VERSION 5.7 ;
  NOWIREEXTENSIONATPIN ON ;
  DIVIDERCHAR "/" ;
  BUSBITCHARS "[]" ;
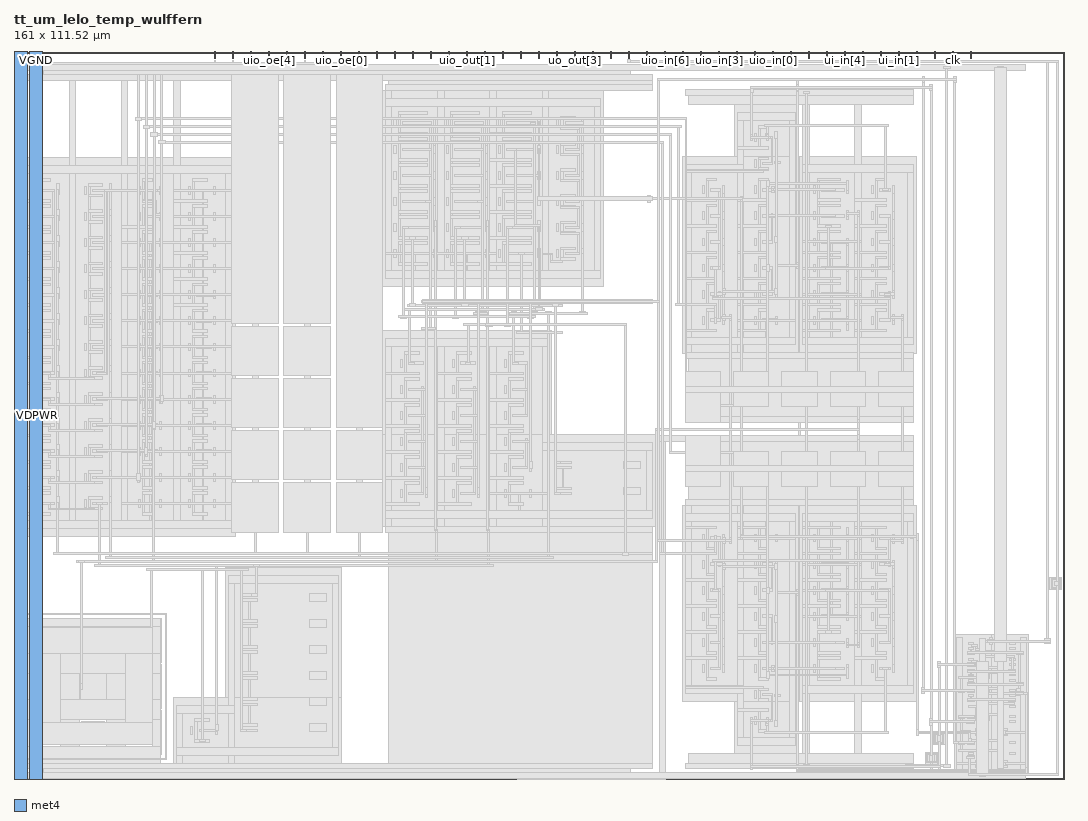
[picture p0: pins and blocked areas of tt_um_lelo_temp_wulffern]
MACRO tt_um_lelo_temp_wulffern
  CLASS BLOCK ;
  FOREIGN tt_um_lelo_temp_wulffern ;
  ORIGIN 0.000 0.000 ;
  SIZE 161.000 BY 111.520 ;
  PIN uio_oe[7]
    DIRECTION OUTPUT ;
    USE SIGNAL ;
    PORT
      LAYER met4 ;
        RECT 30.670 110.520 30.970 111.520 ;
    END
  END uio_oe[7]
  PIN uio_oe[6]
    DIRECTION OUTPUT ;
    USE SIGNAL ;
    PORT
      LAYER met4 ;
        RECT 33.430 110.520 33.730 111.520 ;
    END
  END uio_oe[6]
  PIN uio_oe[5]
    DIRECTION OUTPUT ;
    USE SIGNAL ;
    PORT
      LAYER met4 ;
        RECT 36.190 110.520 36.490 111.520 ;
    END
  END uio_oe[5]
  PIN uio_oe[4]
    DIRECTION OUTPUT ;
    USE SIGNAL ;
    PORT
      LAYER met4 ;
        RECT 38.950 110.520 39.250 111.520 ;
    END
  END uio_oe[4]
  PIN uio_oe[3]
    DIRECTION OUTPUT ;
    USE SIGNAL ;
    PORT
      LAYER met4 ;
        RECT 41.710 110.520 42.010 111.520 ;
    END
  END uio_oe[3]
  PIN uio_oe[2]
    DIRECTION OUTPUT ;
    USE SIGNAL ;
    PORT
      LAYER met4 ;
        RECT 44.470 110.520 44.770 111.520 ;
    END
  END uio_oe[2]
  PIN uio_oe[1]
    DIRECTION OUTPUT ;
    USE SIGNAL ;
    PORT
      LAYER met4 ;
        RECT 47.230 110.520 47.530 111.520 ;
    END
  END uio_oe[1]
  PIN uio_oe[0]
    DIRECTION OUTPUT ;
    USE SIGNAL ;
    PORT
      LAYER met4 ;
        RECT 49.990 110.520 50.290 111.520 ;
    END
  END uio_oe[0]
  PIN VDPWR
    DIRECTION INOUT ;
    USE POWER ;
    PORT
      LAYER met4 ;
        RECT 0.000 0.000 2.000 111.520 ;
    END
  END VDPWR
  PIN VGND
    DIRECTION INOUT ;
    USE GROUND ;
    PORT
      LAYER met4 ;
        RECT 2.400 0.000 4.400 111.520 ;
    END
  END VGND
  PIN ui_in[7]
    DIRECTION INPUT ;
    USE SIGNAL ;
    PORT
      LAYER met4 ;
        RECT 118.990 110.520 119.290 111.520 ;
    END
  END ui_in[7]
  PIN ui_in[6]
    DIRECTION INPUT ;
    USE SIGNAL ;
    PORT
      LAYER met4 ;
        RECT 121.750 110.520 122.050 111.520 ;
    END
  END ui_in[6]
  PIN ui_in[5]
    DIRECTION INPUT ;
    USE SIGNAL ;
    PORT
      LAYER met4 ;
        RECT 124.510 110.520 124.810 111.520 ;
    END
  END ui_in[5]
  PIN ui_in[4]
    DIRECTION INPUT ;
    USE SIGNAL ;
    PORT
      LAYER met4 ;
        RECT 127.270 110.520 127.570 111.520 ;
    END
  END ui_in[4]
  PIN ui_in[3]
    DIRECTION INPUT ;
    USE SIGNAL ;
    PORT
      LAYER met4 ;
        RECT 130.030 110.520 130.330 111.520 ;
    END
  END ui_in[3]
  PIN ui_in[2]
    DIRECTION INPUT ;
    USE SIGNAL ;
    PORT
      LAYER met4 ;
        RECT 132.790 110.520 133.090 111.520 ;
    END
  END ui_in[2]
  PIN ui_in[1]
    DIRECTION INPUT ;
    USE SIGNAL ;
    PORT
      LAYER met4 ;
        RECT 135.550 110.520 135.850 111.520 ;
    END
  END ui_in[1]
  PIN ui_in[0]
    DIRECTION INPUT ;
    USE SIGNAL ;
    ANTENNAGATEAREA 0.490500 ;
    ANTENNADIFFAREA 0.202500 ;
    PORT
      LAYER met4 ;
        RECT 138.310 110.520 138.610 111.520 ;
    END
  END ui_in[0]
  PIN uio_in[7]
    DIRECTION INPUT ;
    USE SIGNAL ;
    PORT
      LAYER met4 ;
        RECT 96.910 110.520 97.210 111.520 ;
    END
  END uio_in[7]
  PIN uio_in[6]
    DIRECTION INPUT ;
    USE SIGNAL ;
    PORT
      LAYER met4 ;
        RECT 99.670 110.520 99.970 111.520 ;
    END
  END uio_in[6]
  PIN uio_in[5]
    DIRECTION INPUT ;
    USE SIGNAL ;
    PORT
      LAYER met4 ;
        RECT 102.430 110.520 102.730 111.520 ;
    END
  END uio_in[5]
  PIN uio_in[4]
    DIRECTION INPUT ;
    USE SIGNAL ;
    PORT
      LAYER met4 ;
        RECT 105.190 110.520 105.490 111.520 ;
    END
  END uio_in[4]
  PIN uio_in[3]
    DIRECTION INPUT ;
    USE SIGNAL ;
    PORT
      LAYER met4 ;
        RECT 107.950 110.520 108.250 111.520 ;
    END
  END uio_in[3]
  PIN uio_in[2]
    DIRECTION INPUT ;
    USE SIGNAL ;
    PORT
      LAYER met4 ;
        RECT 110.710 110.520 111.010 111.520 ;
    END
  END uio_in[2]
  PIN uio_in[1]
    DIRECTION INPUT ;
    USE SIGNAL ;
    PORT
      LAYER met4 ;
        RECT 113.470 110.520 113.770 111.520 ;
    END
  END uio_in[1]
  PIN uio_in[0]
    DIRECTION INPUT ;
    USE SIGNAL ;
    PORT
      LAYER met4 ;
        RECT 116.230 110.520 116.530 111.520 ;
    END
  END uio_in[0]
  PIN ena
    DIRECTION INPUT ;
    USE SIGNAL ;
    PORT
      LAYER met4 ;
        RECT 146.590 110.520 146.890 111.520 ;
    END
  END ena
  PIN rst_n
    DIRECTION INPUT ;
    USE SIGNAL ;
    PORT
      LAYER met4 ;
        RECT 141.070 110.520 141.370 111.520 ;
    END
  END rst_n
  PIN clk
    DIRECTION INPUT ;
    USE SIGNAL ;
    PORT
      LAYER met4 ;
        RECT 143.830 110.520 144.130 111.520 ;
    END
  END clk
  PIN uo_out[7]
    DIRECTION OUTPUT ;
    USE SIGNAL ;
    PORT
      LAYER met4 ;
        RECT 74.830 110.520 75.130 111.520 ;
    END
  END uo_out[7]
  PIN uo_out[6]
    DIRECTION OUTPUT ;
    USE SIGNAL ;
    PORT
      LAYER met4 ;
        RECT 77.590 110.520 77.890 111.520 ;
    END
  END uo_out[6]
  PIN uo_out[5]
    DIRECTION OUTPUT ;
    USE SIGNAL ;
    PORT
      LAYER met4 ;
        RECT 80.350 110.520 80.650 111.520 ;
    END
  END uo_out[5]
  PIN uo_out[4]
    DIRECTION OUTPUT ;
    USE SIGNAL ;
    PORT
      LAYER met4 ;
        RECT 83.110 110.520 83.410 111.520 ;
    END
  END uo_out[4]
  PIN uo_out[3]
    DIRECTION OUTPUT ;
    USE SIGNAL ;
    PORT
      LAYER met4 ;
        RECT 85.870 110.520 86.170 111.520 ;
    END
  END uo_out[3]
  PIN uo_out[2]
    DIRECTION OUTPUT ;
    USE SIGNAL ;
    PORT
      LAYER met4 ;
        RECT 88.630 110.520 88.930 111.520 ;
    END
  END uo_out[2]
  PIN uo_out[1]
    DIRECTION OUTPUT ;
    USE SIGNAL ;
    PORT
      LAYER met4 ;
        RECT 91.390 110.520 91.690 111.520 ;
    END
  END uo_out[1]
  PIN uo_out[0]
    DIRECTION OUTPUT ;
    USE SIGNAL ;
    ANTENNADIFFAREA 0.936000 ;
    PORT
      LAYER met4 ;
        RECT 94.150 110.520 94.450 111.520 ;
    END
  END uo_out[0]
  PIN uio_out[7]
    DIRECTION OUTPUT ;
    USE SIGNAL ;
    PORT
      LAYER met4 ;
        RECT 52.750 110.520 53.050 111.520 ;
    END
  END uio_out[7]
  PIN uio_out[6]
    DIRECTION OUTPUT ;
    USE SIGNAL ;
    PORT
      LAYER met4 ;
        RECT 55.510 110.520 55.810 111.520 ;
    END
  END uio_out[6]
  PIN uio_out[5]
    DIRECTION OUTPUT ;
    USE SIGNAL ;
    PORT
      LAYER met4 ;
        RECT 58.270 110.520 58.570 111.520 ;
    END
  END uio_out[5]
  PIN uio_out[4]
    DIRECTION OUTPUT ;
    USE SIGNAL ;
    PORT
      LAYER met4 ;
        RECT 61.030 110.520 61.330 111.520 ;
    END
  END uio_out[4]
  PIN uio_out[3]
    DIRECTION OUTPUT ;
    USE SIGNAL ;
    PORT
      LAYER met4 ;
        RECT 63.790 110.520 64.090 111.520 ;
    END
  END uio_out[3]
  PIN uio_out[2]
    DIRECTION OUTPUT ;
    USE SIGNAL ;
    PORT
      LAYER met4 ;
        RECT 66.550 110.520 66.850 111.520 ;
    END
  END uio_out[2]
  PIN uio_out[1]
    DIRECTION OUTPUT ;
    USE SIGNAL ;
    PORT
      LAYER met4 ;
        RECT 69.310 110.520 69.610 111.520 ;
    END
  END uio_out[1]
  PIN uio_out[0]
    DIRECTION OUTPUT ;
    USE SIGNAL ;
    PORT
      LAYER met4 ;
        RECT 72.070 110.520 72.370 111.520 ;
    END
  END uio_out[0]
  OBS
      LAYER nwell ;
        RECT 0.060 37.210 33.900 95.290 ;
        RECT 56.540 75.510 90.380 105.590 ;
      LAYER pwell ;
        RECT 110.500 95.390 120.340 103.390 ;
        RECT 56.540 52.790 82.380 68.790 ;
        RECT 102.500 65.310 120.340 95.390 ;
      LAYER nwell ;
        RECT 120.500 65.310 138.340 95.390 ;
      LAYER pwell ;
        RECT 56.540 38.710 98.380 52.790 ;
        RECT 1.665 23.870 8.365 24.635 ;
        RECT 1.665 18.700 2.430 23.870 ;
        RECT 7.600 18.700 8.365 23.870 ;
        RECT 1.665 17.935 8.365 18.700 ;
        RECT 8.765 23.870 15.465 24.635 ;
        RECT 8.765 18.700 9.530 23.870 ;
        RECT 14.700 18.700 15.465 23.870 ;
        RECT 8.765 17.935 15.465 18.700 ;
        RECT 15.865 23.870 22.565 24.635 ;
        RECT 15.865 18.700 16.630 23.870 ;
        RECT 21.800 18.700 22.565 23.870 ;
        RECT 15.865 17.935 22.565 18.700 ;
        RECT 1.665 16.770 8.365 17.535 ;
        RECT 1.665 11.600 2.430 16.770 ;
        RECT 7.600 11.600 8.365 16.770 ;
        RECT 1.665 10.835 8.365 11.600 ;
        RECT 8.765 16.770 15.465 17.535 ;
        RECT 8.765 11.600 9.530 16.770 ;
        RECT 14.700 11.600 15.465 16.770 ;
        RECT 8.765 10.835 15.465 11.600 ;
        RECT 15.865 16.770 22.565 17.535 ;
        RECT 15.865 11.600 16.630 16.770 ;
        RECT 21.800 11.600 22.565 16.770 ;
        RECT 32.430 12.490 50.270 32.490 ;
        RECT 15.865 10.835 22.565 11.600 ;
        RECT 1.665 9.670 8.365 10.435 ;
        RECT 1.665 4.500 2.430 9.670 ;
        RECT 7.600 4.500 8.365 9.670 ;
        RECT 1.665 3.735 8.365 4.500 ;
        RECT 8.765 9.670 15.465 10.435 ;
        RECT 8.765 4.500 9.530 9.670 ;
        RECT 14.700 4.500 15.465 9.670 ;
        RECT 8.765 3.735 15.465 4.500 ;
        RECT 15.865 9.670 22.565 10.435 ;
        RECT 15.865 4.500 16.630 9.670 ;
        RECT 21.800 4.500 22.565 9.670 ;
        RECT 15.865 3.735 22.565 4.500 ;
        RECT 24.430 2.410 50.270 12.490 ;
        RECT 102.500 11.910 120.340 41.990 ;
      LAYER nwell ;
        RECT 120.500 11.910 138.340 41.990 ;
      LAYER pwell ;
        RECT 158.835 29.085 160.665 30.915 ;
        RECT 110.500 3.910 120.340 11.910 ;
        RECT 140.925 5.285 142.755 7.115 ;
        RECT 139.725 2.285 141.555 4.115 ;
        RECT 144.190 0.950 149.890 22.150 ;
      LAYER nwell ;
        RECT 149.890 0.950 155.590 22.150 ;
      LAYER li1 ;
        RECT 0.500 108.610 155.020 109.510 ;
        RECT 4.460 107.950 94.460 108.610 ;
        RECT 0.500 107.050 97.940 107.950 ;
        RECT 0.500 94.050 1.460 107.050 ;
        RECT 8.500 94.050 9.460 107.050 ;
        RECT 16.500 94.050 17.460 107.050 ;
        RECT 24.500 94.050 25.460 107.050 ;
        RECT 57.460 106.450 97.940 107.050 ;
        RECT 56.980 105.550 97.940 106.450 ;
        RECT 56.980 104.350 57.940 105.550 ;
        RECT 64.980 104.350 65.940 105.550 ;
        RECT 72.980 104.350 73.940 105.550 ;
        RECT 80.980 104.350 81.940 105.550 ;
        RECT 102.940 104.850 137.940 105.750 ;
        RECT 56.980 103.150 89.940 104.350 ;
        RECT 103.420 103.350 137.900 104.850 ;
        RECT 0.500 92.850 33.460 94.050 ;
        RECT 0.500 88.850 1.460 92.850 ;
        RECT 3.380 91.650 5.620 92.050 ;
        RECT 2.740 89.650 3.060 90.850 ;
        RECT 3.380 88.850 3.700 91.650 ;
        RECT 6.570 90.850 6.890 91.290 ;
        RECT 6.570 90.450 6.900 90.850 ;
        RECT 4.020 90.050 6.260 90.450 ;
        RECT 0.500 88.450 5.620 88.850 ;
        RECT 0.500 84.850 1.460 88.450 ;
        RECT 3.380 87.650 5.620 88.050 ;
        RECT 2.740 85.650 3.060 86.850 ;
        RECT 3.380 84.850 3.700 87.650 ;
        RECT 5.960 86.450 6.260 90.050 ;
        RECT 6.580 89.650 6.900 90.450 ;
        RECT 6.590 87.290 6.890 89.650 ;
        RECT 6.570 86.850 6.890 87.290 ;
        RECT 6.570 86.450 6.900 86.850 ;
        RECT 4.020 86.050 6.260 86.450 ;
        RECT 0.500 84.450 5.620 84.850 ;
        RECT 0.500 80.850 1.460 84.450 ;
        RECT 3.380 83.650 5.620 84.050 ;
        RECT 2.740 81.650 3.060 82.850 ;
        RECT 3.380 80.850 3.700 83.650 ;
        RECT 5.960 82.450 6.260 86.050 ;
        RECT 6.580 85.650 6.900 86.450 ;
        RECT 6.590 83.290 6.890 85.650 ;
        RECT 6.570 82.850 6.890 83.290 ;
        RECT 6.570 82.450 6.900 82.850 ;
        RECT 4.020 82.050 6.260 82.450 ;
        RECT 0.500 80.450 5.620 80.850 ;
        RECT 0.500 76.850 1.460 80.450 ;
        RECT 3.380 79.650 5.620 80.050 ;
        RECT 2.740 77.650 3.060 78.850 ;
        RECT 3.380 76.850 3.700 79.650 ;
        RECT 5.960 78.450 6.260 82.050 ;
        RECT 6.580 81.650 6.900 82.450 ;
        RECT 6.590 79.290 6.890 81.650 ;
        RECT 6.570 78.850 6.890 79.290 ;
        RECT 6.570 78.450 6.900 78.850 ;
        RECT 4.020 78.050 6.260 78.450 ;
        RECT 0.500 76.450 5.620 76.850 ;
        RECT 0.500 72.850 1.460 76.450 ;
        RECT 3.380 75.650 5.620 76.050 ;
        RECT 2.740 73.650 3.060 74.850 ;
        RECT 3.380 72.850 3.700 75.650 ;
        RECT 5.960 74.450 6.260 78.050 ;
        RECT 6.580 77.650 6.900 78.450 ;
        RECT 6.590 75.290 6.890 77.650 ;
        RECT 6.570 74.850 6.890 75.290 ;
        RECT 6.570 74.450 6.900 74.850 ;
        RECT 4.020 74.050 6.260 74.450 ;
        RECT 0.500 72.450 5.620 72.850 ;
        RECT 0.500 68.850 1.460 72.450 ;
        RECT 3.380 71.650 5.620 72.050 ;
        RECT 2.740 69.650 3.060 70.850 ;
        RECT 3.380 68.850 3.700 71.650 ;
        RECT 5.960 70.450 6.260 74.050 ;
        RECT 6.580 73.650 6.900 74.450 ;
        RECT 6.590 71.290 6.890 73.650 ;
        RECT 6.570 70.850 6.890 71.290 ;
        RECT 6.570 70.450 6.900 70.850 ;
        RECT 4.020 70.050 6.260 70.450 ;
        RECT 0.500 68.450 5.620 68.850 ;
        RECT 0.500 64.850 1.460 68.450 ;
        RECT 3.380 67.650 5.620 68.050 ;
        RECT 2.740 65.650 3.060 66.850 ;
        RECT 3.380 64.850 3.700 67.650 ;
        RECT 5.960 66.450 6.260 70.050 ;
        RECT 6.580 69.650 6.900 70.450 ;
        RECT 6.590 67.290 6.890 69.650 ;
        RECT 6.570 66.850 6.890 67.290 ;
        RECT 6.570 66.450 6.900 66.850 ;
        RECT 4.020 66.050 6.260 66.450 ;
        RECT 0.500 64.450 5.620 64.850 ;
        RECT 0.500 60.850 1.460 64.450 ;
        RECT 3.380 63.650 5.620 64.050 ;
        RECT 2.740 61.650 3.060 62.850 ;
        RECT 3.380 60.850 3.700 63.650 ;
        RECT 5.960 62.450 6.260 66.050 ;
        RECT 6.580 65.650 6.900 66.450 ;
        RECT 6.590 63.290 6.890 65.650 ;
        RECT 6.570 62.850 6.890 63.290 ;
        RECT 6.570 62.450 6.900 62.850 ;
        RECT 4.020 62.050 6.260 62.450 ;
        RECT 6.580 61.650 6.900 62.450 ;
        RECT 0.500 60.450 5.620 60.850 ;
        RECT 0.500 56.850 1.460 60.450 ;
        RECT 3.380 59.650 5.620 60.050 ;
        RECT 2.740 57.650 3.060 58.850 ;
        RECT 3.380 56.850 3.700 59.650 ;
        RECT 6.590 59.290 6.890 61.650 ;
        RECT 6.570 58.850 6.890 59.290 ;
        RECT 6.570 58.450 6.900 58.850 ;
        RECT 4.020 58.050 6.260 58.450 ;
        RECT 6.580 57.650 6.900 58.450 ;
        RECT 0.500 56.450 5.620 56.850 ;
        RECT 0.500 52.850 1.460 56.450 ;
        RECT 3.380 55.650 5.620 56.050 ;
        RECT 2.740 53.650 3.060 54.850 ;
        RECT 3.380 52.850 3.700 55.650 ;
        RECT 6.590 55.290 6.890 57.650 ;
        RECT 6.570 54.850 6.890 55.290 ;
        RECT 6.570 54.450 6.900 54.850 ;
        RECT 4.020 54.050 6.260 54.450 ;
        RECT 6.580 53.650 6.900 54.450 ;
        RECT 0.500 52.450 5.620 52.850 ;
        RECT 0.500 48.850 1.460 52.450 ;
        RECT 3.380 51.650 5.620 52.050 ;
        RECT 2.740 49.650 3.060 50.850 ;
        RECT 3.380 48.850 3.700 51.650 ;
        RECT 6.590 51.290 6.890 53.650 ;
        RECT 6.570 50.850 6.890 51.290 ;
        RECT 6.570 50.450 6.900 50.850 ;
        RECT 4.020 50.050 6.260 50.450 ;
        RECT 6.580 49.650 6.900 50.450 ;
        RECT 0.500 48.450 5.620 48.850 ;
        RECT 0.500 44.850 1.460 48.450 ;
        RECT 3.380 47.650 5.620 48.050 ;
        RECT 2.740 45.650 3.060 46.850 ;
        RECT 3.380 44.850 3.700 47.650 ;
        RECT 6.590 47.290 6.890 49.650 ;
        RECT 6.570 46.850 6.890 47.290 ;
        RECT 6.570 46.450 6.900 46.850 ;
        RECT 4.020 46.050 6.260 46.450 ;
        RECT 6.580 45.650 6.900 46.450 ;
        RECT 0.500 44.450 5.620 44.850 ;
        RECT 0.500 40.850 1.460 44.450 ;
        RECT 3.380 43.650 5.620 44.050 ;
        RECT 2.740 41.650 3.060 42.850 ;
        RECT 3.380 40.850 3.700 43.650 ;
        RECT 6.590 43.290 6.890 45.650 ;
        RECT 6.570 42.850 6.890 43.290 ;
        RECT 6.570 42.450 6.900 42.850 ;
        RECT 4.020 42.050 6.260 42.450 ;
        RECT 6.580 41.650 6.900 42.450 ;
        RECT 0.500 40.450 5.620 40.850 ;
        RECT 0.500 39.650 1.460 40.450 ;
        RECT 8.500 39.650 9.460 92.850 ;
        RECT 11.380 90.850 13.620 91.250 ;
        RECT 14.570 90.850 14.890 91.290 ;
        RECT 10.740 89.650 11.060 90.850 ;
        RECT 11.380 89.650 11.700 90.850 ;
        RECT 14.570 90.450 14.900 90.850 ;
        RECT 12.020 90.050 14.260 90.450 ;
        RECT 11.380 89.250 13.620 89.650 ;
        RECT 11.380 87.250 11.680 89.250 ;
        RECT 11.380 86.850 13.620 87.250 ;
        RECT 10.740 85.650 11.060 86.850 ;
        RECT 11.380 85.650 11.700 86.850 ;
        RECT 13.960 86.450 14.260 90.050 ;
        RECT 14.580 89.650 14.900 90.450 ;
        RECT 14.590 87.290 14.890 89.650 ;
        RECT 14.570 86.850 14.890 87.290 ;
        RECT 14.570 86.450 14.900 86.850 ;
        RECT 12.020 86.050 14.260 86.450 ;
        RECT 11.380 85.250 13.620 85.650 ;
        RECT 11.380 83.250 11.680 85.250 ;
        RECT 11.380 82.850 13.620 83.250 ;
        RECT 10.740 81.650 11.060 82.850 ;
        RECT 11.380 81.650 11.700 82.850 ;
        RECT 13.960 82.450 14.260 86.050 ;
        RECT 14.580 85.650 14.900 86.450 ;
        RECT 14.590 83.290 14.890 85.650 ;
        RECT 14.570 82.850 14.890 83.290 ;
        RECT 16.500 84.850 17.460 92.850 ;
        RECT 19.700 91.650 21.300 92.050 ;
        RECT 19.060 89.650 19.380 90.850 ;
        RECT 19.700 88.850 20.020 91.650 ;
        RECT 22.260 90.450 22.580 90.850 ;
        RECT 20.340 90.050 22.580 90.450 ;
        RECT 22.260 89.650 22.580 90.050 ;
        RECT 24.500 90.400 25.460 92.850 ;
        RECT 27.380 91.650 29.620 92.050 ;
        RECT 26.740 90.400 27.060 90.850 ;
        RECT 27.380 90.400 27.700 91.650 ;
        RECT 30.580 90.450 30.900 90.850 ;
        RECT 28.020 90.400 30.900 90.450 ;
        RECT 32.500 90.400 33.460 92.850 ;
        RECT 24.500 90.100 33.460 90.400 ;
        RECT 24.500 88.850 25.460 90.100 ;
        RECT 26.740 89.650 27.060 90.100 ;
        RECT 27.380 88.850 27.700 90.100 ;
        RECT 28.020 90.050 30.900 90.100 ;
        RECT 28.830 88.850 29.130 90.050 ;
        RECT 30.580 89.650 30.900 90.050 ;
        RECT 19.700 88.750 21.300 88.850 ;
        RECT 19.700 88.450 21.900 88.750 ;
        RECT 19.700 87.650 21.300 88.050 ;
        RECT 19.060 85.650 19.380 86.850 ;
        RECT 19.700 84.850 20.020 87.650 ;
        RECT 21.600 86.750 21.900 88.450 ;
        RECT 24.500 88.450 29.620 88.850 ;
        RECT 22.260 86.750 22.580 86.850 ;
        RECT 21.600 86.450 22.580 86.750 ;
        RECT 20.340 86.050 22.580 86.450 ;
        RECT 22.260 85.650 22.580 86.050 ;
        RECT 24.500 86.400 25.460 88.450 ;
        RECT 28.830 88.050 29.130 88.450 ;
        RECT 27.380 87.650 29.620 88.050 ;
        RECT 26.740 86.400 27.060 86.850 ;
        RECT 27.380 86.400 27.700 87.650 ;
        RECT 28.830 86.450 29.130 87.650 ;
        RECT 30.580 86.450 30.900 86.850 ;
        RECT 28.020 86.400 30.900 86.450 ;
        RECT 32.500 86.400 33.460 90.100 ;
        RECT 24.500 86.100 33.460 86.400 ;
        RECT 24.500 84.850 25.460 86.100 ;
        RECT 26.740 85.650 27.060 86.100 ;
        RECT 27.380 84.850 27.700 86.100 ;
        RECT 28.020 86.050 30.900 86.100 ;
        RECT 28.830 84.850 29.130 86.050 ;
        RECT 30.580 85.650 30.900 86.050 ;
        RECT 16.500 84.450 21.300 84.850 ;
        RECT 24.500 84.450 29.620 84.850 ;
        RECT 14.570 82.450 14.900 82.850 ;
        RECT 12.020 82.050 14.260 82.450 ;
        RECT 11.380 81.250 13.620 81.650 ;
        RECT 11.380 79.250 11.680 81.250 ;
        RECT 11.380 78.850 13.620 79.250 ;
        RECT 10.740 77.650 11.060 78.850 ;
        RECT 11.380 77.650 11.700 78.850 ;
        RECT 13.960 78.450 14.260 82.050 ;
        RECT 14.580 81.650 14.900 82.450 ;
        RECT 16.500 82.400 17.460 84.450 ;
        RECT 19.700 83.650 21.300 84.050 ;
        RECT 19.060 82.400 19.380 82.850 ;
        RECT 19.700 82.400 20.020 83.650 ;
        RECT 20.340 82.400 21.940 82.450 ;
        RECT 22.260 82.400 22.580 82.850 ;
        RECT 24.500 82.400 25.460 84.450 ;
        RECT 28.830 84.050 29.130 84.450 ;
        RECT 27.380 83.650 29.620 84.050 ;
        RECT 26.740 82.400 27.060 82.850 ;
        RECT 27.380 82.400 27.700 83.650 ;
        RECT 28.830 82.450 29.130 83.650 ;
        RECT 30.580 82.450 30.900 82.850 ;
        RECT 28.020 82.400 30.900 82.450 ;
        RECT 32.500 82.400 33.460 86.100 ;
        RECT 16.500 82.100 33.460 82.400 ;
        RECT 14.590 79.290 14.890 81.650 ;
        RECT 14.570 78.850 14.890 79.290 ;
        RECT 14.570 78.450 14.900 78.850 ;
        RECT 12.020 78.050 14.260 78.450 ;
        RECT 11.380 77.250 13.620 77.650 ;
        RECT 11.380 75.250 11.680 77.250 ;
        RECT 11.380 74.850 13.620 75.250 ;
        RECT 10.740 73.650 11.060 74.850 ;
        RECT 11.380 73.650 11.700 74.850 ;
        RECT 13.960 74.450 14.260 78.050 ;
        RECT 14.580 77.650 14.900 78.450 ;
        RECT 16.500 78.400 17.460 82.100 ;
        RECT 19.060 81.650 19.380 82.100 ;
        RECT 19.700 80.850 20.020 82.100 ;
        RECT 20.340 82.050 21.940 82.100 ;
        RECT 20.830 80.850 21.130 82.050 ;
        RECT 22.260 81.650 22.580 82.100 ;
        RECT 24.500 80.850 25.460 82.100 ;
        RECT 26.740 81.650 27.060 82.100 ;
        RECT 27.380 80.850 27.700 82.100 ;
        RECT 28.020 82.050 30.900 82.100 ;
        RECT 28.830 80.850 29.130 82.050 ;
        RECT 30.580 81.650 30.900 82.050 ;
        RECT 19.700 80.450 21.300 80.850 ;
        RECT 24.500 80.450 29.620 80.850 ;
        RECT 20.830 80.050 21.130 80.450 ;
        RECT 19.700 79.650 21.300 80.050 ;
        RECT 19.060 78.400 19.380 78.850 ;
        RECT 19.700 78.400 20.020 79.650 ;
        RECT 20.830 78.450 21.130 79.650 ;
        RECT 20.340 78.400 21.940 78.450 ;
        RECT 22.260 78.400 22.580 78.850 ;
        RECT 24.500 78.400 25.460 80.450 ;
        RECT 28.830 80.050 29.130 80.450 ;
        RECT 27.380 79.650 29.620 80.050 ;
        RECT 26.740 78.400 27.060 78.850 ;
        RECT 27.380 78.400 27.700 79.650 ;
        RECT 28.830 78.450 29.130 79.650 ;
        RECT 30.580 78.450 30.900 78.850 ;
        RECT 28.020 78.400 30.900 78.450 ;
        RECT 32.500 78.400 33.460 82.100 ;
        RECT 16.500 78.100 33.460 78.400 ;
        RECT 14.590 75.290 14.890 77.650 ;
        RECT 14.570 74.850 14.890 75.290 ;
        RECT 14.570 74.450 14.900 74.850 ;
        RECT 12.020 74.050 14.260 74.450 ;
        RECT 11.380 73.250 13.620 73.650 ;
        RECT 11.380 71.250 11.680 73.250 ;
        RECT 11.380 70.850 13.620 71.250 ;
        RECT 10.740 69.650 11.060 70.850 ;
        RECT 11.380 69.650 11.700 70.850 ;
        RECT 13.960 70.450 14.260 74.050 ;
        RECT 14.580 73.650 14.900 74.450 ;
        RECT 16.500 74.400 17.460 78.100 ;
        RECT 19.060 77.650 19.380 78.100 ;
        RECT 19.700 76.850 20.020 78.100 ;
        RECT 20.340 78.050 21.940 78.100 ;
        RECT 20.830 76.850 21.130 78.050 ;
        RECT 22.260 77.650 22.580 78.100 ;
        RECT 24.500 76.850 25.460 78.100 ;
        RECT 26.740 77.650 27.060 78.100 ;
        RECT 27.380 76.850 27.700 78.100 ;
        RECT 28.020 78.050 30.900 78.100 ;
        RECT 28.830 76.850 29.130 78.050 ;
        RECT 30.580 77.650 30.900 78.050 ;
        RECT 19.700 76.450 21.300 76.850 ;
        RECT 24.500 76.450 29.620 76.850 ;
        RECT 20.830 76.050 21.130 76.450 ;
        RECT 19.700 75.650 21.300 76.050 ;
        RECT 19.060 74.400 19.380 74.850 ;
        RECT 19.700 74.400 20.020 75.650 ;
        RECT 20.830 74.450 21.130 75.650 ;
        RECT 20.340 74.400 21.940 74.450 ;
        RECT 22.260 74.400 22.580 74.850 ;
        RECT 24.500 74.400 25.460 76.450 ;
        RECT 28.830 76.050 29.130 76.450 ;
        RECT 27.380 75.650 29.620 76.050 ;
        RECT 26.740 74.400 27.060 74.850 ;
        RECT 27.380 74.400 27.700 75.650 ;
        RECT 28.830 74.450 29.130 75.650 ;
        RECT 30.580 74.450 30.900 74.850 ;
        RECT 28.020 74.400 30.900 74.450 ;
        RECT 32.500 74.400 33.460 78.100 ;
        RECT 56.980 80.700 57.940 103.150 ;
        RECT 58.900 101.950 63.380 102.350 ;
        RECT 58.260 99.950 58.580 101.150 ;
        RECT 58.900 99.150 59.220 101.950 ;
        RECT 59.540 100.350 64.020 100.750 ;
        RECT 58.900 98.750 63.380 99.150 ;
        RECT 58.900 98.350 59.200 98.750 ;
        RECT 58.900 97.950 63.380 98.350 ;
        RECT 58.260 95.950 58.580 97.150 ;
        RECT 58.900 95.150 59.220 97.950 ;
        RECT 63.720 96.750 64.020 100.350 ;
        RECT 64.340 99.950 64.660 101.150 ;
        RECT 64.350 97.150 64.650 99.950 ;
        RECT 59.540 96.350 64.020 96.750 ;
        RECT 58.900 94.750 63.380 95.150 ;
        RECT 58.900 94.350 59.200 94.750 ;
        RECT 58.900 93.950 63.380 94.350 ;
        RECT 58.260 91.950 58.580 93.150 ;
        RECT 58.900 91.150 59.220 93.950 ;
        RECT 63.720 92.750 64.020 96.350 ;
        RECT 64.340 95.950 64.660 97.150 ;
        RECT 64.350 93.150 64.650 95.950 ;
        RECT 59.540 92.350 64.020 92.750 ;
        RECT 58.900 90.750 63.380 91.150 ;
        RECT 58.900 90.350 59.200 90.750 ;
        RECT 58.900 89.950 63.380 90.350 ;
        RECT 58.260 87.950 58.580 89.150 ;
        RECT 58.900 87.150 59.220 89.950 ;
        RECT 63.720 88.750 64.020 92.350 ;
        RECT 64.340 91.950 64.660 93.150 ;
        RECT 64.350 89.150 64.650 91.950 ;
        RECT 59.540 88.350 64.020 88.750 ;
        RECT 64.340 87.950 64.660 89.150 ;
        RECT 58.900 86.750 63.380 87.150 ;
        RECT 58.900 86.350 59.200 86.750 ;
        RECT 58.900 85.950 63.380 86.350 ;
        RECT 58.260 83.950 58.580 85.150 ;
        RECT 58.900 83.150 59.220 85.950 ;
        RECT 64.350 85.590 64.650 87.950 ;
        RECT 64.350 85.150 64.810 85.590 ;
        RECT 64.340 84.750 64.810 85.150 ;
        RECT 59.540 84.350 64.020 84.750 ;
        RECT 64.340 83.950 64.660 84.750 ;
        RECT 58.900 82.750 63.380 83.150 ;
        RECT 58.900 81.950 63.380 82.350 ;
        RECT 58.260 80.700 58.580 81.150 ;
        RECT 58.900 80.700 59.220 81.950 ;
        RECT 59.540 80.700 64.020 80.750 ;
        RECT 64.340 80.700 64.660 81.150 ;
        RECT 64.980 80.700 65.940 103.150 ;
        RECT 66.900 101.950 71.380 102.350 ;
        RECT 66.260 99.950 66.580 101.150 ;
        RECT 66.900 99.150 67.220 101.950 ;
        RECT 67.540 100.350 72.020 100.750 ;
        RECT 66.900 98.750 71.380 99.150 ;
        RECT 66.900 98.350 67.200 98.750 ;
        RECT 66.900 97.950 71.380 98.350 ;
        RECT 66.260 95.950 66.580 97.150 ;
        RECT 66.900 95.150 67.220 97.950 ;
        RECT 71.720 96.750 72.020 100.350 ;
        RECT 72.340 99.950 72.660 101.150 ;
        RECT 72.350 97.150 72.650 99.950 ;
        RECT 72.980 99.150 73.940 103.150 ;
        RECT 74.900 101.950 79.380 102.350 ;
        RECT 74.260 99.950 74.580 101.150 ;
        RECT 74.900 99.150 75.220 101.950 ;
        RECT 80.340 101.130 80.660 101.150 ;
        RECT 80.300 100.750 80.680 101.130 ;
        RECT 75.540 100.350 80.020 100.750 ;
        RECT 80.340 99.950 80.660 100.750 ;
        RECT 72.980 98.750 79.380 99.150 ;
        RECT 67.540 96.350 72.020 96.750 ;
        RECT 66.900 94.750 71.380 95.150 ;
        RECT 66.900 94.350 67.200 94.750 ;
        RECT 66.900 93.950 71.380 94.350 ;
        RECT 66.260 91.950 66.580 93.150 ;
        RECT 66.900 91.150 67.220 93.950 ;
        RECT 71.720 92.750 72.020 96.350 ;
        RECT 72.340 95.950 72.660 97.150 ;
        RECT 72.350 93.150 72.650 95.950 ;
        RECT 72.980 95.150 73.940 98.750 ;
        RECT 74.900 97.950 79.380 98.350 ;
        RECT 74.260 95.950 74.580 97.150 ;
        RECT 74.900 95.150 75.220 97.950 ;
        RECT 80.340 97.130 80.660 97.150 ;
        RECT 80.300 96.750 80.680 97.130 ;
        RECT 75.540 96.350 80.020 96.750 ;
        RECT 72.980 94.750 79.380 95.150 ;
        RECT 67.540 92.350 72.020 92.750 ;
        RECT 66.900 90.750 71.380 91.150 ;
        RECT 66.900 90.350 67.200 90.750 ;
        RECT 66.900 89.950 71.380 90.350 ;
        RECT 66.260 87.950 66.580 89.150 ;
        RECT 66.900 87.150 67.220 89.950 ;
        RECT 71.720 88.750 72.020 92.350 ;
        RECT 72.340 91.950 72.660 93.150 ;
        RECT 72.350 89.150 72.650 91.950 ;
        RECT 72.980 91.150 73.940 94.750 ;
        RECT 74.900 93.950 79.380 94.350 ;
        RECT 74.260 91.950 74.580 93.150 ;
        RECT 74.900 91.150 75.220 93.950 ;
        RECT 79.720 92.750 80.020 96.350 ;
        RECT 80.340 95.950 80.660 96.750 ;
        RECT 80.340 92.750 80.660 93.150 ;
        RECT 75.540 92.350 80.660 92.750 ;
        RECT 80.340 91.950 80.660 92.350 ;
        RECT 72.980 90.750 79.380 91.150 ;
        RECT 67.540 88.350 72.020 88.750 ;
        RECT 72.340 87.950 72.660 89.150 ;
        RECT 66.900 86.750 71.380 87.150 ;
        RECT 66.900 86.350 67.200 86.750 ;
        RECT 66.900 85.950 71.380 86.350 ;
        RECT 66.260 83.950 66.580 85.150 ;
        RECT 66.900 83.150 67.220 85.950 ;
        RECT 72.350 85.590 72.650 87.950 ;
        RECT 72.980 87.150 73.940 90.750 ;
        RECT 74.900 89.950 79.380 90.350 ;
        RECT 74.260 87.950 74.580 89.150 ;
        RECT 74.900 87.150 75.220 89.950 ;
        RECT 80.340 89.130 80.660 89.150 ;
        RECT 80.300 88.750 80.680 89.130 ;
        RECT 75.540 88.350 80.020 88.750 ;
        RECT 72.980 86.750 79.380 87.150 ;
        RECT 72.350 85.150 72.810 85.590 ;
        RECT 72.340 84.750 72.810 85.150 ;
        RECT 67.540 84.350 72.020 84.750 ;
        RECT 72.340 83.950 72.660 84.750 ;
        RECT 72.980 83.150 73.940 86.750 ;
        RECT 74.900 85.950 79.380 86.350 ;
        RECT 74.260 83.950 74.580 85.150 ;
        RECT 74.900 83.150 75.220 85.950 ;
        RECT 79.720 84.750 80.020 88.350 ;
        RECT 80.340 87.950 80.660 88.750 ;
        RECT 75.540 84.350 80.020 84.750 ;
        RECT 80.340 83.950 80.660 85.590 ;
        RECT 66.900 82.750 71.380 83.150 ;
        RECT 72.980 82.750 79.380 83.150 ;
        RECT 66.900 81.950 71.380 82.350 ;
        RECT 66.260 80.700 66.580 81.150 ;
        RECT 66.900 80.700 67.220 81.950 ;
        RECT 67.540 80.700 72.020 80.750 ;
        RECT 72.340 80.700 72.660 81.150 ;
        RECT 72.980 80.700 73.940 82.750 ;
        RECT 74.900 81.950 79.380 82.350 ;
        RECT 56.980 80.400 73.940 80.700 ;
        RECT 56.980 77.950 57.940 80.400 ;
        RECT 58.260 79.950 58.580 80.400 ;
        RECT 58.900 79.150 59.220 80.400 ;
        RECT 59.540 80.350 64.020 80.400 ;
        RECT 61.310 79.150 61.610 80.350 ;
        RECT 64.340 79.950 64.660 80.400 ;
        RECT 58.900 78.750 63.380 79.150 ;
        RECT 61.310 77.950 61.610 78.750 ;
        RECT 64.980 77.950 65.940 80.400 ;
        RECT 66.260 79.950 66.580 80.400 ;
        RECT 66.900 79.150 67.220 80.400 ;
        RECT 67.540 80.350 72.020 80.400 ;
        RECT 69.310 79.150 69.610 80.350 ;
        RECT 72.340 79.950 72.660 80.400 ;
        RECT 72.980 79.150 73.940 80.400 ;
        RECT 74.260 79.950 74.580 81.150 ;
        RECT 74.900 79.150 75.220 81.950 ;
        RECT 80.320 81.150 80.640 81.350 ;
        RECT 75.540 80.350 80.020 80.750 ;
        RECT 80.320 80.510 80.660 81.150 ;
        RECT 80.340 79.950 80.660 80.510 ;
        RECT 80.980 80.650 81.940 103.150 ;
        RECT 83.860 101.150 86.100 101.550 ;
        RECT 83.220 99.950 83.540 101.150 ;
        RECT 83.860 99.950 84.180 101.150 ;
        RECT 87.060 100.750 87.380 101.150 ;
        RECT 84.500 100.350 87.380 100.750 ;
        RECT 87.060 99.950 87.380 100.350 ;
        RECT 83.860 99.850 86.100 99.950 ;
        RECT 83.860 99.550 86.700 99.850 ;
        RECT 83.860 97.150 86.100 97.550 ;
        RECT 83.220 95.950 83.540 97.150 ;
        RECT 83.860 95.950 84.180 97.150 ;
        RECT 86.400 96.750 86.700 99.550 ;
        RECT 87.070 97.150 87.370 99.950 ;
        RECT 84.500 96.350 86.740 96.750 ;
        RECT 87.060 95.950 87.380 97.150 ;
        RECT 83.860 95.850 86.100 95.950 ;
        RECT 83.860 95.550 86.700 95.850 ;
        RECT 83.860 93.150 86.100 93.550 ;
        RECT 83.220 91.950 83.540 93.150 ;
        RECT 83.860 91.950 84.180 93.150 ;
        RECT 86.400 92.750 86.700 95.550 ;
        RECT 87.070 93.150 87.370 95.950 ;
        RECT 84.500 92.350 86.740 92.750 ;
        RECT 87.060 91.950 87.380 93.150 ;
        RECT 83.860 91.850 86.100 91.950 ;
        RECT 83.860 91.550 86.700 91.850 ;
        RECT 83.860 89.150 86.100 89.550 ;
        RECT 83.220 87.950 83.540 89.150 ;
        RECT 83.860 87.950 84.180 89.150 ;
        RECT 86.400 88.750 86.700 91.550 ;
        RECT 87.070 89.150 87.370 91.950 ;
        RECT 84.500 88.350 86.740 88.750 ;
        RECT 87.060 87.950 87.380 89.150 ;
        RECT 83.860 87.850 86.100 87.950 ;
        RECT 83.860 87.550 86.700 87.850 ;
        RECT 83.860 85.150 86.100 85.550 ;
        RECT 83.220 83.950 83.540 85.150 ;
        RECT 83.860 83.950 84.180 85.150 ;
        RECT 86.400 84.750 86.700 87.550 ;
        RECT 87.070 85.150 87.370 87.950 ;
        RECT 84.500 84.350 86.740 84.750 ;
        RECT 87.060 83.950 87.380 85.150 ;
        RECT 83.860 83.850 86.100 83.950 ;
        RECT 83.860 83.550 86.700 83.850 ;
        RECT 83.860 81.150 86.100 81.550 ;
        RECT 80.980 80.350 82.540 80.650 ;
        RECT 66.900 78.750 71.380 79.150 ;
        RECT 72.980 78.750 79.380 79.150 ;
        RECT 69.310 77.950 69.610 78.750 ;
        RECT 72.980 77.950 73.940 78.750 ;
        RECT 80.980 77.950 81.940 80.350 ;
        RECT 82.240 79.550 82.540 80.350 ;
        RECT 83.220 79.950 83.540 81.150 ;
        RECT 83.860 79.950 84.180 81.150 ;
        RECT 86.400 80.750 86.700 83.550 ;
        RECT 87.070 81.350 87.370 83.950 ;
        RECT 87.050 81.150 87.370 81.350 ;
        RECT 84.500 80.350 86.740 80.750 ;
        RECT 87.050 80.510 87.380 81.150 ;
        RECT 87.060 79.950 87.380 80.510 ;
        RECT 83.860 79.550 86.100 79.950 ;
        RECT 82.240 79.250 84.160 79.550 ;
        RECT 88.980 77.950 89.940 103.150 ;
        RECT 110.940 100.950 119.900 102.150 ;
        RECT 110.940 96.950 111.900 100.950 ;
        RECT 114.140 99.750 115.740 100.150 ;
        RECT 113.500 97.750 113.820 98.950 ;
        RECT 114.140 96.950 114.460 99.750 ;
        RECT 115.170 98.550 115.490 98.990 ;
        RECT 116.670 98.950 116.990 99.110 ;
        RECT 114.780 98.150 116.380 98.550 ;
        RECT 116.670 98.270 117.020 98.950 ;
        RECT 110.940 96.550 115.740 96.950 ;
        RECT 110.940 94.150 111.900 96.550 ;
        RECT 114.140 94.950 115.740 95.350 ;
        RECT 56.980 76.750 89.940 77.950 ;
        RECT 102.940 93.450 111.900 94.150 ;
        RECT 113.500 93.750 113.820 94.950 ;
        RECT 114.140 93.750 114.460 94.950 ;
        RECT 116.080 94.550 116.380 98.150 ;
        RECT 116.700 97.750 117.020 98.270 ;
        RECT 116.690 94.950 117.010 95.150 ;
        RECT 116.690 94.660 117.020 94.950 ;
        RECT 114.780 94.150 116.380 94.550 ;
        RECT 116.660 94.340 117.500 94.660 ;
        RECT 116.690 94.310 117.020 94.340 ;
        RECT 116.700 93.750 117.020 94.310 ;
        RECT 114.140 93.450 115.740 93.750 ;
        RECT 102.940 93.350 115.740 93.450 ;
        RECT 102.940 93.050 114.940 93.350 ;
        RECT 102.940 92.950 111.900 93.050 ;
        RECT 102.940 88.950 103.900 92.950 ;
        RECT 106.140 91.750 107.740 92.150 ;
        RECT 105.500 89.750 105.820 90.950 ;
        RECT 106.140 88.950 106.460 91.750 ;
        RECT 106.780 90.150 108.380 90.550 ;
        RECT 102.940 88.550 107.740 88.950 ;
        RECT 102.940 84.950 103.900 88.550 ;
        RECT 106.140 87.750 107.740 88.150 ;
        RECT 105.500 85.750 105.820 86.950 ;
        RECT 106.140 84.950 106.460 87.750 ;
        RECT 108.080 86.550 108.380 90.150 ;
        RECT 108.700 89.750 109.020 90.950 ;
        RECT 108.710 86.950 109.010 89.750 ;
        RECT 110.940 88.950 111.900 92.950 ;
        RECT 114.140 91.750 115.740 92.150 ;
        RECT 113.500 89.750 113.820 90.950 ;
        RECT 114.140 88.950 114.460 91.750 ;
        RECT 116.210 90.550 116.530 90.750 ;
        RECT 114.780 90.150 116.530 90.550 ;
        RECT 116.210 89.910 116.530 90.150 ;
        RECT 116.700 89.750 117.020 90.950 ;
        RECT 110.940 88.550 115.740 88.950 ;
        RECT 106.780 86.150 108.380 86.550 ;
        RECT 102.940 84.550 107.740 84.950 ;
        RECT 102.940 80.950 103.900 84.550 ;
        RECT 106.140 83.750 107.740 84.150 ;
        RECT 105.500 81.750 105.820 82.950 ;
        RECT 106.140 80.950 106.460 83.750 ;
        RECT 108.080 82.550 108.380 86.150 ;
        RECT 108.700 85.750 109.020 86.950 ;
        RECT 108.710 82.950 109.010 85.750 ;
        RECT 110.940 84.950 111.900 88.550 ;
        RECT 114.140 87.750 115.740 88.150 ;
        RECT 113.500 85.750 113.820 86.950 ;
        RECT 114.140 84.950 114.460 87.750 ;
        RECT 116.710 86.950 117.010 89.750 ;
        RECT 116.080 86.550 116.380 86.750 ;
        RECT 116.700 86.550 117.020 86.950 ;
        RECT 114.780 86.150 117.020 86.550 ;
        RECT 110.940 84.550 115.740 84.950 ;
        RECT 106.780 82.150 108.380 82.550 ;
        RECT 102.940 80.550 107.740 80.950 ;
        RECT 102.940 76.950 103.900 80.550 ;
        RECT 106.140 79.750 107.740 80.150 ;
        RECT 105.500 77.750 105.820 78.950 ;
        RECT 106.140 76.950 106.460 79.750 ;
        RECT 108.080 78.550 108.380 82.150 ;
        RECT 108.700 81.750 109.020 82.950 ;
        RECT 108.710 78.950 109.010 81.750 ;
        RECT 110.940 80.950 111.900 84.550 ;
        RECT 114.140 83.750 115.740 84.150 ;
        RECT 113.500 81.750 113.820 82.950 ;
        RECT 114.140 80.950 114.460 83.750 ;
        RECT 116.080 82.550 116.380 86.150 ;
        RECT 116.700 85.750 117.020 86.150 ;
        RECT 114.780 82.150 116.380 82.550 ;
        RECT 116.670 82.950 116.990 83.110 ;
        RECT 116.670 82.270 117.020 82.950 ;
        RECT 116.700 81.750 117.020 82.270 ;
        RECT 110.940 80.550 115.740 80.950 ;
        RECT 106.780 78.150 108.380 78.550 ;
        RECT 108.700 77.750 109.020 78.950 ;
        RECT 16.500 74.100 33.460 74.400 ;
        RECT 14.590 71.290 14.890 73.650 ;
        RECT 14.570 70.850 14.890 71.290 ;
        RECT 14.570 70.450 14.900 70.850 ;
        RECT 12.020 70.050 14.260 70.450 ;
        RECT 11.380 69.250 13.620 69.650 ;
        RECT 11.380 67.250 11.680 69.250 ;
        RECT 11.380 66.850 13.620 67.250 ;
        RECT 10.740 65.650 11.060 66.850 ;
        RECT 11.380 65.650 11.700 66.850 ;
        RECT 13.960 66.450 14.260 70.050 ;
        RECT 14.580 69.650 14.900 70.450 ;
        RECT 16.500 70.400 17.460 74.100 ;
        RECT 19.060 73.650 19.380 74.100 ;
        RECT 19.700 72.850 20.020 74.100 ;
        RECT 20.340 74.050 21.940 74.100 ;
        RECT 20.830 72.850 21.130 74.050 ;
        RECT 22.260 73.650 22.580 74.100 ;
        RECT 24.500 72.850 25.460 74.100 ;
        RECT 26.740 73.650 27.060 74.100 ;
        RECT 27.380 72.850 27.700 74.100 ;
        RECT 28.020 74.050 30.900 74.100 ;
        RECT 28.830 72.850 29.130 74.050 ;
        RECT 30.580 73.650 30.900 74.050 ;
        RECT 19.700 72.450 21.300 72.850 ;
        RECT 24.500 72.450 29.620 72.850 ;
        RECT 20.830 72.050 21.130 72.450 ;
        RECT 19.700 71.650 21.300 72.050 ;
        RECT 19.060 70.400 19.380 70.850 ;
        RECT 19.700 70.400 20.020 71.650 ;
        RECT 20.830 70.450 21.130 71.650 ;
        RECT 20.340 70.400 21.940 70.450 ;
        RECT 22.260 70.400 22.580 70.850 ;
        RECT 24.500 70.400 25.460 72.450 ;
        RECT 28.830 72.050 29.130 72.450 ;
        RECT 27.380 71.650 29.620 72.050 ;
        RECT 26.740 70.400 27.060 70.850 ;
        RECT 27.380 70.400 27.700 71.650 ;
        RECT 28.830 70.450 29.130 71.650 ;
        RECT 28.020 70.400 30.260 70.450 ;
        RECT 30.580 70.400 30.900 70.850 ;
        RECT 32.500 70.400 33.460 74.100 ;
        RECT 16.500 70.100 33.460 70.400 ;
        RECT 14.590 67.290 14.890 69.650 ;
        RECT 14.570 66.850 14.890 67.290 ;
        RECT 14.570 66.450 14.900 66.850 ;
        RECT 12.020 66.050 14.260 66.450 ;
        RECT 11.380 65.250 13.620 65.650 ;
        RECT 11.380 63.250 11.680 65.250 ;
        RECT 11.380 62.850 13.620 63.250 ;
        RECT 10.740 61.650 11.060 62.850 ;
        RECT 11.380 61.650 11.700 62.850 ;
        RECT 13.960 62.450 14.260 66.050 ;
        RECT 14.580 65.650 14.900 66.450 ;
        RECT 16.500 66.400 17.460 70.100 ;
        RECT 19.060 69.650 19.380 70.100 ;
        RECT 19.700 68.850 20.020 70.100 ;
        RECT 20.340 70.050 21.940 70.100 ;
        RECT 20.830 68.850 21.130 70.050 ;
        RECT 22.260 69.650 22.580 70.100 ;
        RECT 19.700 68.450 21.300 68.850 ;
        RECT 20.830 68.050 21.130 68.450 ;
        RECT 19.700 67.650 21.300 68.050 ;
        RECT 19.060 66.400 19.380 66.850 ;
        RECT 19.700 66.400 20.020 67.650 ;
        RECT 20.830 66.450 21.130 67.650 ;
        RECT 20.340 66.400 21.940 66.450 ;
        RECT 22.260 66.400 22.580 66.850 ;
        RECT 24.500 66.400 25.460 70.100 ;
        RECT 26.740 69.650 27.060 70.100 ;
        RECT 27.380 68.850 27.700 70.100 ;
        RECT 28.020 70.050 30.260 70.100 ;
        RECT 28.830 68.850 29.130 70.050 ;
        RECT 30.580 69.650 30.900 70.100 ;
        RECT 27.380 68.450 29.620 68.850 ;
        RECT 28.830 68.050 29.130 68.450 ;
        RECT 27.380 67.650 29.620 68.050 ;
        RECT 26.740 66.400 27.060 66.850 ;
        RECT 27.380 66.400 27.700 67.650 ;
        RECT 28.830 66.450 29.130 67.650 ;
        RECT 28.020 66.400 30.260 66.450 ;
        RECT 30.580 66.400 30.900 66.850 ;
        RECT 32.500 66.400 33.460 70.100 ;
        RECT 102.940 76.550 107.740 76.950 ;
        RECT 102.940 72.950 103.900 76.550 ;
        RECT 106.140 75.750 107.740 76.150 ;
        RECT 105.500 73.750 105.820 74.950 ;
        RECT 106.140 72.950 106.460 75.750 ;
        RECT 108.710 74.950 109.010 77.750 ;
        RECT 110.940 76.950 111.900 80.550 ;
        RECT 114.140 79.750 115.740 80.150 ;
        RECT 113.500 77.750 113.820 78.950 ;
        RECT 114.140 76.950 114.460 79.750 ;
        RECT 116.690 78.950 117.010 79.150 ;
        RECT 115.410 78.550 115.730 78.750 ;
        RECT 114.780 78.150 116.380 78.550 ;
        RECT 116.690 78.310 117.020 78.950 ;
        RECT 115.410 77.910 115.730 78.150 ;
        RECT 110.940 76.550 115.740 76.950 ;
        RECT 108.080 74.550 108.380 74.750 ;
        RECT 108.700 74.550 109.020 74.950 ;
        RECT 106.780 74.150 109.020 74.550 ;
        RECT 102.940 72.550 107.740 72.950 ;
        RECT 102.940 68.950 103.900 72.550 ;
        RECT 106.140 71.750 107.740 72.150 ;
        RECT 105.500 69.750 105.820 70.950 ;
        RECT 106.140 68.950 106.460 71.750 ;
        RECT 107.410 70.550 107.730 70.750 ;
        RECT 108.080 70.550 108.380 74.150 ;
        RECT 108.700 73.750 109.020 74.150 ;
        RECT 110.940 72.950 111.900 76.550 ;
        RECT 114.140 75.750 115.740 76.150 ;
        RECT 113.500 73.750 113.820 74.950 ;
        RECT 114.140 72.950 114.460 75.750 ;
        RECT 116.080 74.550 116.380 78.150 ;
        RECT 116.700 77.750 117.020 78.310 ;
        RECT 114.780 74.150 116.380 74.550 ;
        RECT 116.670 74.950 116.990 75.110 ;
        RECT 116.670 74.270 117.020 74.950 ;
        RECT 116.700 73.750 117.020 74.270 ;
        RECT 110.940 72.550 115.740 72.950 ;
        RECT 106.780 70.150 108.380 70.550 ;
        RECT 108.690 70.950 109.010 71.150 ;
        RECT 108.690 70.310 109.020 70.950 ;
        RECT 107.410 69.910 107.730 70.150 ;
        RECT 108.700 69.750 109.020 70.310 ;
        RECT 110.940 70.500 111.900 72.550 ;
        RECT 114.140 71.750 115.740 72.150 ;
        RECT 113.500 70.500 113.820 70.950 ;
        RECT 114.140 70.500 114.460 71.750 ;
        RECT 116.700 70.550 117.020 70.950 ;
        RECT 114.780 70.500 117.020 70.550 ;
        RECT 118.940 70.500 119.900 100.950 ;
        RECT 110.940 70.200 119.900 70.500 ;
        RECT 110.940 68.950 111.900 70.200 ;
        RECT 113.500 69.750 113.820 70.200 ;
        RECT 114.140 68.950 114.460 70.200 ;
        RECT 114.780 70.150 117.020 70.200 ;
        RECT 115.270 68.950 115.570 70.150 ;
        RECT 116.700 69.750 117.020 70.150 ;
        RECT 102.940 68.550 107.740 68.950 ;
        RECT 110.940 68.550 115.740 68.950 ;
        RECT 102.940 67.750 103.900 68.550 ;
        RECT 110.940 67.750 111.900 68.550 ;
        RECT 115.270 67.750 115.570 68.550 ;
        RECT 118.940 67.750 119.900 70.200 ;
        RECT 16.500 66.100 33.460 66.400 ;
        RECT 14.590 63.290 14.890 65.650 ;
        RECT 14.570 62.850 14.890 63.290 ;
        RECT 14.570 62.450 14.900 62.850 ;
        RECT 12.020 62.050 14.260 62.450 ;
        RECT 14.580 61.650 14.900 62.450 ;
        RECT 16.500 62.400 17.460 66.100 ;
        RECT 19.060 65.650 19.380 66.100 ;
        RECT 19.700 64.850 20.020 66.100 ;
        RECT 20.340 66.050 21.940 66.100 ;
        RECT 20.830 64.850 21.130 66.050 ;
        RECT 22.260 65.650 22.580 66.100 ;
        RECT 19.700 64.450 21.300 64.850 ;
        RECT 20.830 64.050 21.130 64.450 ;
        RECT 19.700 63.650 21.300 64.050 ;
        RECT 19.060 62.400 19.380 62.850 ;
        RECT 19.700 62.400 20.020 63.650 ;
        RECT 20.830 62.450 21.130 63.650 ;
        RECT 20.340 62.400 21.940 62.450 ;
        RECT 22.260 62.400 22.580 62.850 ;
        RECT 24.500 62.400 25.460 66.100 ;
        RECT 26.740 65.650 27.060 66.100 ;
        RECT 27.380 64.850 27.700 66.100 ;
        RECT 28.020 66.050 30.260 66.100 ;
        RECT 28.830 64.850 29.130 66.050 ;
        RECT 30.580 65.650 30.900 66.100 ;
        RECT 27.380 64.450 29.620 64.850 ;
        RECT 28.830 64.050 29.130 64.450 ;
        RECT 27.380 63.650 29.620 64.050 ;
        RECT 26.740 62.400 27.060 62.850 ;
        RECT 27.380 62.400 27.700 63.650 ;
        RECT 28.830 62.450 29.130 63.650 ;
        RECT 28.020 62.400 30.260 62.450 ;
        RECT 30.580 62.400 30.900 62.850 ;
        RECT 32.500 62.400 33.460 66.100 ;
        RECT 16.500 62.100 33.460 62.400 ;
        RECT 11.380 61.250 13.620 61.650 ;
        RECT 14.590 59.290 14.890 61.650 ;
        RECT 11.380 58.850 13.620 59.250 ;
        RECT 14.570 58.850 14.890 59.290 ;
        RECT 10.740 57.650 11.060 58.850 ;
        RECT 11.380 57.650 11.700 58.850 ;
        RECT 14.570 58.450 14.900 58.850 ;
        RECT 12.020 58.050 14.260 58.450 ;
        RECT 14.580 57.650 14.900 58.450 ;
        RECT 16.500 58.400 17.460 62.100 ;
        RECT 19.060 61.650 19.380 62.100 ;
        RECT 19.700 60.850 20.020 62.100 ;
        RECT 20.340 62.050 21.940 62.100 ;
        RECT 20.830 60.850 21.130 62.050 ;
        RECT 22.260 61.650 22.580 62.100 ;
        RECT 19.700 60.450 21.300 60.850 ;
        RECT 20.830 60.050 21.130 60.450 ;
        RECT 19.700 59.650 21.300 60.050 ;
        RECT 19.060 58.400 19.380 58.850 ;
        RECT 19.700 58.400 20.020 59.650 ;
        RECT 20.830 58.450 21.130 59.650 ;
        RECT 20.340 58.400 21.940 58.450 ;
        RECT 22.260 58.400 22.580 58.850 ;
        RECT 24.500 58.400 25.460 62.100 ;
        RECT 26.740 61.650 27.060 62.100 ;
        RECT 27.380 60.850 27.700 62.100 ;
        RECT 28.020 62.050 30.260 62.100 ;
        RECT 28.830 60.850 29.130 62.050 ;
        RECT 30.580 61.650 30.900 62.100 ;
        RECT 27.380 60.450 29.620 60.850 ;
        RECT 28.830 60.050 29.130 60.450 ;
        RECT 27.380 59.650 29.620 60.050 ;
        RECT 26.740 58.400 27.060 58.850 ;
        RECT 27.380 58.400 27.700 59.650 ;
        RECT 28.830 58.450 29.130 59.650 ;
        RECT 28.020 58.400 30.260 58.450 ;
        RECT 30.580 58.400 30.900 58.850 ;
        RECT 32.500 58.400 33.460 62.100 ;
        RECT 16.500 58.100 33.460 58.400 ;
        RECT 11.380 57.250 13.620 57.650 ;
        RECT 14.590 55.290 14.890 57.650 ;
        RECT 11.380 54.850 13.620 55.250 ;
        RECT 14.570 54.850 14.890 55.290 ;
        RECT 10.740 53.650 11.060 54.850 ;
        RECT 11.380 53.650 11.700 54.850 ;
        RECT 14.570 54.450 14.900 54.850 ;
        RECT 12.020 54.050 14.260 54.450 ;
        RECT 14.580 53.650 14.900 54.450 ;
        RECT 16.500 54.400 17.460 58.100 ;
        RECT 19.060 57.650 19.380 58.100 ;
        RECT 19.700 56.850 20.020 58.100 ;
        RECT 20.340 58.050 21.940 58.100 ;
        RECT 20.830 56.850 21.130 58.050 ;
        RECT 22.260 57.650 22.580 58.100 ;
        RECT 19.700 56.450 21.300 56.850 ;
        RECT 20.830 56.050 21.130 56.450 ;
        RECT 19.700 55.650 21.300 56.050 ;
        RECT 19.060 54.400 19.380 54.850 ;
        RECT 19.700 54.400 20.020 55.650 ;
        RECT 20.830 54.450 21.130 55.650 ;
        RECT 20.340 54.400 21.940 54.450 ;
        RECT 22.260 54.400 22.580 54.850 ;
        RECT 24.500 54.400 25.460 58.100 ;
        RECT 26.740 57.650 27.060 58.100 ;
        RECT 27.380 56.850 27.700 58.100 ;
        RECT 28.020 58.050 30.260 58.100 ;
        RECT 28.830 56.850 29.130 58.050 ;
        RECT 30.580 57.650 30.900 58.100 ;
        RECT 27.380 56.450 29.620 56.850 ;
        RECT 28.830 56.050 29.130 56.450 ;
        RECT 27.380 55.650 29.620 56.050 ;
        RECT 26.740 54.400 27.060 54.850 ;
        RECT 27.380 54.400 27.700 55.650 ;
        RECT 28.830 54.450 29.130 55.650 ;
        RECT 28.020 54.400 30.260 54.450 ;
        RECT 30.580 54.400 30.900 54.850 ;
        RECT 32.500 54.400 33.460 58.100 ;
        RECT 16.500 54.100 33.460 54.400 ;
        RECT 11.380 53.250 13.620 53.650 ;
        RECT 14.590 51.290 14.890 53.650 ;
        RECT 11.380 50.850 13.620 51.250 ;
        RECT 14.570 50.850 14.890 51.290 ;
        RECT 10.740 49.650 11.060 50.850 ;
        RECT 11.380 49.650 11.700 50.850 ;
        RECT 14.570 50.450 14.900 50.850 ;
        RECT 12.020 50.050 14.260 50.450 ;
        RECT 14.580 49.650 14.900 50.450 ;
        RECT 16.500 50.400 17.460 54.100 ;
        RECT 19.060 53.650 19.380 54.100 ;
        RECT 19.700 52.850 20.020 54.100 ;
        RECT 20.340 54.050 21.940 54.100 ;
        RECT 20.830 52.850 21.130 54.050 ;
        RECT 22.260 53.650 22.580 54.100 ;
        RECT 19.700 52.450 21.300 52.850 ;
        RECT 20.830 52.050 21.130 52.450 ;
        RECT 19.700 51.650 21.300 52.050 ;
        RECT 19.060 50.400 19.380 50.850 ;
        RECT 19.700 50.400 20.020 51.650 ;
        RECT 20.830 50.450 21.130 51.650 ;
        RECT 20.340 50.400 21.940 50.450 ;
        RECT 22.260 50.400 22.580 50.850 ;
        RECT 24.500 50.400 25.460 54.100 ;
        RECT 26.740 53.650 27.060 54.100 ;
        RECT 27.380 52.850 27.700 54.100 ;
        RECT 28.020 54.050 30.260 54.100 ;
        RECT 28.830 52.850 29.130 54.050 ;
        RECT 30.580 53.650 30.900 54.100 ;
        RECT 27.380 52.450 29.620 52.850 ;
        RECT 28.830 52.050 29.130 52.450 ;
        RECT 27.380 51.650 29.620 52.050 ;
        RECT 26.740 50.400 27.060 50.850 ;
        RECT 27.380 50.400 27.700 51.650 ;
        RECT 28.830 50.450 29.130 51.650 ;
        RECT 28.020 50.400 30.260 50.450 ;
        RECT 30.580 50.400 30.900 50.850 ;
        RECT 32.500 50.400 33.460 54.100 ;
        RECT 16.500 50.100 33.460 50.400 ;
        RECT 11.380 49.250 13.620 49.650 ;
        RECT 14.590 47.290 14.890 49.650 ;
        RECT 11.380 46.850 13.620 47.250 ;
        RECT 14.570 46.850 14.890 47.290 ;
        RECT 10.740 45.650 11.060 46.850 ;
        RECT 11.380 45.650 11.700 46.850 ;
        RECT 14.570 46.450 14.900 46.850 ;
        RECT 12.020 46.050 14.260 46.450 ;
        RECT 14.580 45.650 14.900 46.450 ;
        RECT 16.500 46.400 17.460 50.100 ;
        RECT 19.060 49.650 19.380 50.100 ;
        RECT 19.700 48.850 20.020 50.100 ;
        RECT 20.340 50.050 21.940 50.100 ;
        RECT 20.830 48.850 21.130 50.050 ;
        RECT 22.260 49.650 22.580 50.100 ;
        RECT 19.700 48.450 21.300 48.850 ;
        RECT 20.830 48.050 21.130 48.450 ;
        RECT 19.700 47.650 21.300 48.050 ;
        RECT 19.060 46.400 19.380 46.850 ;
        RECT 19.700 46.400 20.020 47.650 ;
        RECT 20.830 46.450 21.130 47.650 ;
        RECT 20.340 46.400 21.940 46.450 ;
        RECT 22.260 46.400 22.580 46.850 ;
        RECT 24.500 46.400 25.460 50.100 ;
        RECT 26.740 49.650 27.060 50.100 ;
        RECT 27.380 48.850 27.700 50.100 ;
        RECT 28.020 50.050 30.260 50.100 ;
        RECT 28.830 48.850 29.130 50.050 ;
        RECT 30.580 49.650 30.900 50.100 ;
        RECT 27.380 48.450 29.620 48.850 ;
        RECT 28.830 48.050 29.130 48.450 ;
        RECT 27.380 47.650 29.620 48.050 ;
        RECT 26.740 46.400 27.060 46.850 ;
        RECT 27.380 46.400 27.700 47.650 ;
        RECT 28.830 46.450 29.130 47.650 ;
        RECT 28.020 46.400 30.260 46.450 ;
        RECT 30.580 46.400 30.900 46.850 ;
        RECT 32.500 46.400 33.460 50.100 ;
        RECT 16.500 46.100 33.460 46.400 ;
        RECT 11.380 45.250 13.620 45.650 ;
        RECT 14.590 43.290 14.890 45.650 ;
        RECT 11.380 42.850 13.620 43.250 ;
        RECT 14.570 42.850 14.890 43.290 ;
        RECT 10.740 41.650 11.060 42.850 ;
        RECT 11.380 41.650 11.700 42.850 ;
        RECT 14.570 42.450 14.900 42.850 ;
        RECT 12.020 42.050 14.260 42.450 ;
        RECT 14.580 41.650 14.900 42.450 ;
        RECT 16.500 42.400 17.460 46.100 ;
        RECT 19.060 45.650 19.380 46.100 ;
        RECT 19.700 44.850 20.020 46.100 ;
        RECT 20.340 46.050 21.940 46.100 ;
        RECT 20.830 44.850 21.130 46.050 ;
        RECT 22.260 45.650 22.580 46.100 ;
        RECT 19.700 44.450 21.300 44.850 ;
        RECT 20.830 44.050 21.130 44.450 ;
        RECT 19.700 43.650 21.300 44.050 ;
        RECT 19.060 42.400 19.380 42.850 ;
        RECT 19.700 42.400 20.020 43.650 ;
        RECT 20.830 42.450 21.130 43.650 ;
        RECT 20.340 42.400 21.940 42.450 ;
        RECT 22.260 42.400 22.580 42.850 ;
        RECT 24.500 42.400 25.460 46.100 ;
        RECT 26.740 45.650 27.060 46.100 ;
        RECT 27.380 44.850 27.700 46.100 ;
        RECT 28.020 46.050 30.260 46.100 ;
        RECT 28.830 44.850 29.130 46.050 ;
        RECT 30.580 45.650 30.900 46.100 ;
        RECT 27.380 44.450 29.620 44.850 ;
        RECT 28.830 44.050 29.130 44.450 ;
        RECT 27.380 43.650 29.620 44.050 ;
        RECT 26.740 42.400 27.060 42.850 ;
        RECT 27.380 42.400 27.700 43.650 ;
        RECT 28.830 42.450 29.130 43.650 ;
        RECT 28.020 42.400 30.260 42.450 ;
        RECT 30.580 42.400 30.900 42.850 ;
        RECT 32.500 42.400 33.460 46.100 ;
        RECT 16.500 42.100 33.460 42.400 ;
        RECT 11.380 41.250 13.620 41.650 ;
        RECT 16.500 39.650 17.460 42.100 ;
        RECT 19.060 41.650 19.380 42.100 ;
        RECT 19.700 40.850 20.020 42.100 ;
        RECT 20.340 42.050 21.940 42.100 ;
        RECT 20.830 40.850 21.130 42.050 ;
        RECT 22.260 41.650 22.580 42.100 ;
        RECT 19.700 40.450 21.300 40.850 ;
        RECT 20.830 39.650 21.130 40.450 ;
        RECT 24.500 39.650 25.460 42.100 ;
        RECT 26.740 41.650 27.060 42.100 ;
        RECT 27.380 40.850 27.700 42.100 ;
        RECT 28.020 42.050 30.260 42.100 ;
        RECT 28.830 40.850 29.130 42.050 ;
        RECT 30.580 41.650 30.900 42.100 ;
        RECT 27.380 40.450 29.620 40.850 ;
        RECT 28.830 39.650 29.130 40.450 ;
        RECT 32.500 39.650 33.460 42.100 ;
        RECT 0.500 38.450 33.460 39.650 ;
        RECT 56.980 66.350 81.940 67.550 ;
        RECT 56.980 62.350 57.940 66.350 ;
        RECT 59.860 65.150 62.100 65.550 ;
        RECT 59.220 63.150 59.540 64.350 ;
        RECT 59.860 62.350 60.180 65.150 ;
        RECT 63.050 64.350 63.370 64.550 ;
        RECT 60.500 63.550 62.740 63.950 ;
        RECT 63.050 63.710 63.380 64.350 ;
        RECT 63.060 63.150 63.380 63.710 ;
        RECT 56.980 61.950 62.100 62.350 ;
        RECT 56.980 58.350 57.940 61.950 ;
        RECT 59.860 61.150 62.100 61.550 ;
        RECT 59.220 59.150 59.540 60.350 ;
        RECT 59.860 58.350 60.180 61.150 ;
        RECT 63.070 60.350 63.370 63.150 ;
        RECT 64.980 62.350 65.940 66.350 ;
        RECT 67.860 65.150 70.100 65.550 ;
        RECT 67.220 63.150 67.540 64.350 ;
        RECT 67.860 62.350 68.180 65.150 ;
        RECT 71.040 64.350 71.360 64.550 ;
        RECT 68.500 63.550 70.740 63.950 ;
        RECT 71.040 63.710 71.380 64.350 ;
        RECT 71.060 63.150 71.380 63.710 ;
        RECT 64.980 61.950 70.100 62.350 ;
        RECT 62.440 59.950 62.740 60.150 ;
        RECT 63.060 59.950 63.380 60.350 ;
        RECT 60.500 59.550 63.380 59.950 ;
        RECT 56.980 57.950 62.100 58.350 ;
        RECT 56.980 54.350 57.940 57.950 ;
        RECT 59.860 57.150 62.100 57.550 ;
        RECT 59.220 55.150 59.540 56.350 ;
        RECT 59.860 54.350 60.180 57.150 ;
        RECT 62.440 55.950 62.740 59.550 ;
        RECT 63.060 59.150 63.380 59.550 ;
        RECT 63.070 56.350 63.370 59.150 ;
        RECT 64.980 58.350 65.940 61.950 ;
        RECT 67.860 61.150 70.100 61.550 ;
        RECT 67.220 59.150 67.540 60.350 ;
        RECT 67.860 58.350 68.180 61.150 ;
        RECT 71.070 60.350 71.370 63.150 ;
        RECT 72.980 62.350 73.940 66.350 ;
        RECT 75.860 65.150 78.100 65.550 ;
        RECT 75.220 63.150 75.540 64.350 ;
        RECT 75.860 62.350 76.180 65.150 ;
        RECT 79.040 64.350 79.360 64.550 ;
        RECT 76.500 63.550 78.740 63.950 ;
        RECT 79.040 63.710 79.380 64.350 ;
        RECT 72.980 61.950 78.100 62.350 ;
        RECT 70.440 59.950 70.740 60.150 ;
        RECT 71.060 59.950 71.380 60.350 ;
        RECT 68.500 59.550 71.380 59.950 ;
        RECT 64.980 57.950 70.100 58.350 ;
        RECT 63.060 55.950 63.380 56.350 ;
        RECT 60.500 55.550 63.380 55.950 ;
        RECT 56.980 53.950 62.100 54.350 ;
        RECT 56.980 50.350 57.940 53.950 ;
        RECT 59.860 53.150 62.100 53.550 ;
        RECT 59.220 51.150 59.540 52.350 ;
        RECT 59.860 50.350 60.180 53.150 ;
        RECT 62.440 51.950 62.740 55.550 ;
        RECT 63.060 55.150 63.380 55.550 ;
        RECT 63.070 52.350 63.370 55.150 ;
        RECT 64.980 54.350 65.940 57.950 ;
        RECT 67.860 57.150 70.100 57.550 ;
        RECT 67.220 55.150 67.540 56.350 ;
        RECT 67.860 54.350 68.180 57.150 ;
        RECT 70.440 55.950 70.740 59.550 ;
        RECT 71.060 59.150 71.380 59.550 ;
        RECT 71.070 56.350 71.370 59.150 ;
        RECT 72.980 58.350 73.940 61.950 ;
        RECT 75.860 61.150 78.100 61.550 ;
        RECT 75.220 59.150 75.540 60.350 ;
        RECT 75.860 58.350 76.180 61.150 ;
        RECT 78.440 59.950 78.740 63.550 ;
        RECT 79.060 63.150 79.380 63.710 ;
        RECT 79.070 60.350 79.370 63.150 ;
        RECT 76.500 59.550 78.740 59.950 ;
        RECT 72.980 57.950 78.100 58.350 ;
        RECT 71.060 55.950 71.380 56.350 ;
        RECT 68.500 55.550 71.380 55.950 ;
        RECT 64.980 53.950 70.100 54.350 ;
        RECT 63.060 51.950 63.380 52.350 ;
        RECT 60.500 51.550 63.380 51.950 ;
        RECT 56.980 49.950 62.100 50.350 ;
        RECT 56.980 46.350 57.940 49.950 ;
        RECT 59.860 49.150 62.100 49.550 ;
        RECT 59.220 47.150 59.540 48.350 ;
        RECT 59.860 46.350 60.180 49.150 ;
        RECT 62.440 47.950 62.740 51.550 ;
        RECT 63.060 51.150 63.380 51.550 ;
        RECT 63.070 48.350 63.370 51.150 ;
        RECT 64.980 50.350 65.940 53.950 ;
        RECT 67.860 53.150 70.100 53.550 ;
        RECT 67.220 51.150 67.540 52.350 ;
        RECT 67.860 50.350 68.180 53.150 ;
        RECT 70.440 51.950 70.740 55.550 ;
        RECT 71.060 55.150 71.380 55.550 ;
        RECT 71.070 52.350 71.370 55.150 ;
        RECT 72.980 54.350 73.940 57.950 ;
        RECT 75.860 57.150 78.100 57.550 ;
        RECT 75.220 55.150 75.540 56.350 ;
        RECT 75.860 54.350 76.180 57.150 ;
        RECT 78.440 55.950 78.740 59.550 ;
        RECT 79.060 59.150 79.380 60.350 ;
        RECT 79.070 56.350 79.370 59.150 ;
        RECT 76.500 55.550 78.740 55.950 ;
        RECT 79.060 55.150 79.380 56.350 ;
        RECT 72.980 53.950 78.100 54.350 ;
        RECT 71.060 51.950 71.380 52.350 ;
        RECT 68.500 51.550 71.380 51.950 ;
        RECT 64.980 49.950 70.100 50.350 ;
        RECT 63.060 47.950 63.380 48.350 ;
        RECT 60.500 47.550 63.380 47.950 ;
        RECT 56.980 45.950 62.100 46.350 ;
        RECT 56.980 42.350 57.940 45.950 ;
        RECT 59.860 45.150 62.100 45.550 ;
        RECT 59.220 43.150 59.540 44.350 ;
        RECT 59.860 42.350 60.180 45.150 ;
        RECT 62.440 43.950 62.740 47.550 ;
        RECT 63.060 47.150 63.380 47.550 ;
        RECT 64.980 46.350 65.940 49.950 ;
        RECT 67.860 49.150 70.100 49.550 ;
        RECT 67.220 47.150 67.540 48.350 ;
        RECT 67.860 46.350 68.180 49.150 ;
        RECT 70.440 47.950 70.740 51.550 ;
        RECT 71.060 51.150 71.380 51.550 ;
        RECT 71.070 48.350 71.370 51.150 ;
        RECT 72.980 50.350 73.940 53.950 ;
        RECT 75.860 53.150 78.100 53.550 ;
        RECT 75.220 51.150 75.540 52.350 ;
        RECT 75.860 50.350 76.180 53.150 ;
        RECT 79.070 52.350 79.370 55.150 ;
        RECT 78.440 51.950 78.740 52.150 ;
        RECT 79.060 51.950 79.380 52.350 ;
        RECT 76.500 51.550 79.380 51.950 ;
        RECT 72.980 49.950 78.100 50.350 ;
        RECT 71.060 47.950 71.380 48.350 ;
        RECT 68.500 47.550 71.380 47.950 ;
        RECT 64.980 45.950 70.100 46.350 ;
        RECT 60.500 43.550 62.740 43.950 ;
        RECT 63.060 43.150 63.380 44.510 ;
        RECT 64.980 42.350 65.940 45.950 ;
        RECT 67.860 45.150 70.100 45.550 ;
        RECT 67.220 43.150 67.540 44.350 ;
        RECT 67.860 42.350 68.180 45.150 ;
        RECT 70.440 43.950 70.740 47.550 ;
        RECT 71.060 47.150 71.380 47.550 ;
        RECT 72.980 46.350 73.940 49.950 ;
        RECT 75.860 49.150 78.100 49.550 ;
        RECT 75.220 47.150 75.540 48.350 ;
        RECT 75.860 46.350 76.180 49.150 ;
        RECT 78.440 47.950 78.740 51.550 ;
        RECT 79.060 51.150 79.380 51.550 ;
        RECT 80.980 51.550 81.940 66.350 ;
        RECT 102.940 66.550 119.900 67.750 ;
        RECT 120.940 94.150 121.900 103.350 ;
        RECT 128.940 94.150 129.900 103.350 ;
        RECT 120.940 92.950 137.900 94.150 ;
        RECT 120.940 82.500 121.900 92.950 ;
        RECT 123.180 91.750 126.700 92.150 ;
        RECT 122.540 89.750 122.860 90.950 ;
        RECT 123.180 88.950 123.500 91.750 ;
        RECT 127.650 90.950 127.970 91.150 ;
        RECT 123.820 90.150 127.340 90.550 ;
        RECT 127.650 90.310 127.980 90.950 ;
        RECT 127.660 89.750 127.980 90.310 ;
        RECT 128.940 88.950 129.900 92.950 ;
        RECT 132.140 91.750 133.740 92.150 ;
        RECT 131.500 89.750 131.820 90.950 ;
        RECT 132.140 88.950 132.460 91.750 ;
        RECT 132.780 90.150 134.380 90.550 ;
        RECT 134.700 89.750 135.020 90.950 ;
        RECT 123.180 88.550 126.700 88.950 ;
        RECT 128.940 88.550 133.740 88.950 ;
        RECT 123.180 88.150 123.480 88.550 ;
        RECT 123.180 87.750 126.700 88.150 ;
        RECT 122.540 85.750 122.860 86.950 ;
        RECT 123.180 84.950 123.500 87.750 ;
        RECT 127.650 86.950 127.970 87.150 ;
        RECT 123.820 86.150 127.340 86.550 ;
        RECT 127.650 86.310 127.980 86.950 ;
        RECT 127.660 85.750 127.980 86.310 ;
        RECT 128.940 84.950 129.900 88.550 ;
        RECT 132.140 87.750 133.740 88.150 ;
        RECT 131.500 85.750 131.820 86.950 ;
        RECT 132.140 84.950 132.460 87.750 ;
        RECT 134.710 86.950 135.010 89.750 ;
        RECT 132.780 86.150 134.380 86.550 ;
        RECT 123.180 84.550 126.700 84.950 ;
        RECT 128.940 84.550 133.740 84.950 ;
        RECT 123.180 83.750 126.700 84.150 ;
        RECT 122.540 82.500 122.860 82.950 ;
        RECT 123.180 82.500 123.500 83.750 ;
        RECT 127.660 82.550 127.980 82.950 ;
        RECT 123.820 82.500 127.980 82.550 ;
        RECT 128.940 82.500 129.900 84.550 ;
        RECT 132.140 83.750 133.740 84.150 ;
        RECT 120.940 82.200 129.900 82.500 ;
        RECT 120.940 80.950 121.900 82.200 ;
        RECT 122.540 81.750 122.860 82.200 ;
        RECT 123.180 80.950 123.500 82.200 ;
        RECT 123.820 82.150 127.980 82.200 ;
        RECT 125.270 80.950 125.570 82.150 ;
        RECT 127.660 81.750 127.980 82.150 ;
        RECT 120.940 80.550 126.700 80.950 ;
        RECT 120.940 78.500 121.900 80.550 ;
        RECT 125.270 80.150 125.570 80.550 ;
        RECT 123.180 79.750 126.700 80.150 ;
        RECT 122.540 78.500 122.860 78.950 ;
        RECT 123.180 78.500 123.500 79.750 ;
        RECT 125.270 78.550 125.570 79.750 ;
        RECT 127.670 78.950 127.970 81.750 ;
        RECT 128.940 80.950 129.900 82.200 ;
        RECT 131.500 81.750 131.820 82.950 ;
        RECT 132.140 80.950 132.460 83.750 ;
        RECT 134.080 82.550 134.380 86.150 ;
        RECT 134.700 85.750 135.020 86.950 ;
        RECT 134.710 82.950 135.010 85.750 ;
        RECT 132.780 82.150 134.380 82.550 ;
        RECT 128.940 80.550 133.740 80.950 ;
        RECT 127.660 78.550 127.980 78.950 ;
        RECT 123.820 78.500 127.980 78.550 ;
        RECT 128.940 78.500 129.900 80.550 ;
        RECT 132.140 79.750 133.740 80.150 ;
        RECT 120.940 78.200 129.900 78.500 ;
        RECT 120.940 76.950 121.900 78.200 ;
        RECT 122.540 77.750 122.860 78.200 ;
        RECT 123.180 76.950 123.500 78.200 ;
        RECT 123.820 78.150 127.980 78.200 ;
        RECT 125.270 76.950 125.570 78.150 ;
        RECT 127.660 77.750 127.980 78.150 ;
        RECT 120.940 76.550 126.700 76.950 ;
        RECT 120.940 74.500 121.900 76.550 ;
        RECT 125.270 76.150 125.570 76.550 ;
        RECT 123.180 75.750 126.700 76.150 ;
        RECT 122.540 74.500 122.860 74.950 ;
        RECT 123.180 74.500 123.500 75.750 ;
        RECT 125.270 74.550 125.570 75.750 ;
        RECT 127.670 74.950 127.970 77.750 ;
        RECT 128.940 76.950 129.900 78.200 ;
        RECT 131.500 77.750 131.820 78.950 ;
        RECT 132.140 76.950 132.460 79.750 ;
        RECT 134.080 78.550 134.380 82.150 ;
        RECT 134.700 81.750 135.020 82.950 ;
        RECT 134.710 78.950 135.010 81.750 ;
        RECT 132.780 78.150 134.380 78.550 ;
        RECT 134.700 77.750 135.020 78.950 ;
        RECT 128.940 76.550 133.740 76.950 ;
        RECT 127.660 74.550 127.980 74.950 ;
        RECT 123.820 74.500 127.980 74.550 ;
        RECT 128.940 74.500 129.900 76.550 ;
        RECT 132.140 75.750 133.740 76.150 ;
        RECT 120.940 74.200 129.900 74.500 ;
        RECT 120.940 72.950 121.900 74.200 ;
        RECT 122.540 73.750 122.860 74.200 ;
        RECT 123.180 72.950 123.500 74.200 ;
        RECT 123.820 74.150 127.980 74.200 ;
        RECT 125.270 72.950 125.570 74.150 ;
        RECT 127.660 73.750 127.980 74.150 ;
        RECT 120.940 72.550 126.700 72.950 ;
        RECT 120.940 70.500 121.900 72.550 ;
        RECT 125.270 72.150 125.570 72.550 ;
        RECT 123.180 71.750 126.700 72.150 ;
        RECT 122.540 70.500 122.860 70.950 ;
        RECT 123.180 70.500 123.500 71.750 ;
        RECT 125.270 70.550 125.570 71.750 ;
        RECT 127.670 70.950 127.970 73.750 ;
        RECT 128.940 72.950 129.900 74.200 ;
        RECT 131.500 73.750 131.820 74.950 ;
        RECT 132.140 72.950 132.460 75.750 ;
        RECT 134.710 74.950 135.010 77.750 ;
        RECT 134.080 74.550 134.380 74.750 ;
        RECT 134.700 74.550 135.020 74.950 ;
        RECT 132.780 74.150 135.020 74.550 ;
        RECT 128.940 72.550 133.740 72.950 ;
        RECT 127.660 70.550 127.980 70.950 ;
        RECT 123.820 70.500 127.980 70.550 ;
        RECT 128.940 70.500 129.900 72.550 ;
        RECT 132.140 71.750 133.740 72.150 ;
        RECT 120.940 70.200 129.900 70.500 ;
        RECT 120.940 68.950 121.900 70.200 ;
        RECT 122.540 69.750 122.860 70.200 ;
        RECT 123.180 68.950 123.500 70.200 ;
        RECT 123.820 70.150 127.980 70.200 ;
        RECT 125.270 68.950 125.570 70.150 ;
        RECT 127.660 69.750 127.980 70.150 ;
        RECT 120.940 68.550 126.700 68.950 ;
        RECT 127.670 68.750 127.970 69.750 ;
        RECT 128.940 68.950 129.900 70.200 ;
        RECT 131.500 69.750 131.820 70.950 ;
        RECT 132.140 68.950 132.460 71.750 ;
        RECT 134.080 70.550 134.380 74.150 ;
        RECT 134.700 73.750 135.020 74.150 ;
        RECT 132.780 70.150 134.380 70.550 ;
        RECT 134.690 70.950 135.010 71.150 ;
        RECT 134.690 70.310 135.020 70.950 ;
        RECT 134.700 69.750 135.020 70.310 ;
        RECT 128.940 68.550 133.740 68.950 ;
        RECT 120.940 67.750 121.900 68.550 ;
        RECT 125.270 67.750 125.570 68.550 ;
        RECT 128.940 67.750 129.900 68.550 ;
        RECT 136.940 67.750 137.900 92.950 ;
        RECT 120.940 66.550 137.900 67.750 ;
        RECT 102.940 65.350 103.900 66.550 ;
        RECT 110.940 65.350 111.900 66.550 ;
        RECT 102.940 64.450 137.900 65.350 ;
        RECT 103.420 55.550 137.900 64.450 ;
        RECT 102.940 54.650 137.940 55.550 ;
        RECT 98.940 52.650 102.940 52.700 ;
        RECT 120.290 52.650 120.590 54.650 ;
        RECT 98.940 51.750 137.940 52.650 ;
        RECT 98.940 51.700 102.940 51.750 ;
        RECT 80.980 50.350 97.940 51.550 ;
        RECT 76.500 47.550 78.740 47.950 ;
        RECT 79.060 47.150 79.380 48.510 ;
        RECT 72.980 45.950 78.100 46.350 ;
        RECT 68.500 43.550 70.740 43.950 ;
        RECT 71.060 43.150 71.380 44.510 ;
        RECT 72.980 43.900 73.940 45.950 ;
        RECT 75.860 45.150 78.100 45.550 ;
        RECT 75.220 43.900 75.540 44.350 ;
        RECT 75.860 43.900 76.180 45.150 ;
        RECT 76.500 43.900 78.740 43.950 ;
        RECT 79.060 43.900 79.380 44.350 ;
        RECT 80.980 43.900 81.940 50.350 ;
        RECT 82.900 48.350 85.460 48.750 ;
        RECT 82.900 47.550 85.460 47.950 ;
        RECT 93.460 47.550 96.020 48.750 ;
        RECT 84.030 44.750 84.330 47.550 ;
        RECT 82.900 44.350 85.460 44.750 ;
        RECT 72.980 43.600 81.940 43.900 ;
        RECT 56.980 41.950 62.100 42.350 ;
        RECT 64.980 41.950 70.100 42.350 ;
        RECT 56.980 41.150 57.940 41.950 ;
        RECT 64.980 41.150 65.940 41.950 ;
        RECT 72.980 41.150 73.940 43.600 ;
        RECT 75.220 43.150 75.540 43.600 ;
        RECT 75.860 42.350 76.180 43.600 ;
        RECT 76.500 43.550 78.740 43.600 ;
        RECT 77.310 42.350 77.610 43.550 ;
        RECT 79.060 43.150 79.380 43.600 ;
        RECT 75.860 41.950 78.100 42.350 ;
        RECT 77.310 41.150 77.610 41.950 ;
        RECT 80.980 41.150 81.940 43.600 ;
        RECT 82.900 43.550 85.460 43.950 ;
        RECT 93.460 43.550 96.020 44.750 ;
        RECT 96.980 41.150 97.940 50.350 ;
        RECT 56.980 39.950 97.940 41.150 ;
        RECT 56.980 38.750 57.940 39.950 ;
        RECT 64.980 38.750 65.940 39.950 ;
        RECT 72.980 38.750 73.940 39.950 ;
        RECT 80.980 38.750 81.940 39.950 ;
        RECT 56.980 37.850 97.940 38.750 ;
        RECT 32.870 30.050 49.830 31.250 ;
        RECT 0.980 25.250 23.350 25.420 ;
        RECT 0.980 3.220 1.150 25.250 ;
        RECT 1.765 23.330 22.465 24.535 ;
        RECT 1.765 19.240 2.970 23.330 ;
        RECT 3.280 19.550 6.750 23.020 ;
        RECT 7.060 19.240 10.070 23.330 ;
        RECT 10.380 19.550 13.850 23.020 ;
        RECT 14.160 19.240 17.170 23.330 ;
        RECT 17.480 19.550 20.950 23.020 ;
        RECT 21.260 19.240 22.465 23.330 ;
        RECT 1.765 16.230 22.465 19.240 ;
        RECT 1.765 12.140 2.970 16.230 ;
        RECT 3.280 12.450 6.750 15.920 ;
        RECT 7.060 12.140 10.070 16.230 ;
        RECT 10.380 12.450 13.850 15.920 ;
        RECT 14.160 12.140 17.170 16.230 ;
        RECT 17.480 12.450 20.950 15.920 ;
        RECT 21.260 12.140 22.465 16.230 ;
        RECT 1.765 9.130 22.465 12.140 ;
        RECT 1.765 5.040 2.970 9.130 ;
        RECT 3.280 5.350 6.750 8.820 ;
        RECT 7.060 5.040 10.070 9.130 ;
        RECT 10.380 5.350 13.850 8.820 ;
        RECT 14.160 5.040 17.170 9.130 ;
        RECT 17.480 5.350 20.950 8.820 ;
        RECT 21.260 5.040 22.465 9.130 ;
        RECT 1.765 3.220 22.465 5.040 ;
        RECT 23.180 3.220 23.350 25.250 ;
        RECT 32.870 11.250 33.830 30.050 ;
        RECT 34.790 28.050 37.350 28.450 ;
        RECT 34.790 27.250 37.350 27.650 ;
        RECT 45.350 27.250 47.910 28.450 ;
        RECT 35.920 24.450 36.220 27.250 ;
        RECT 34.790 24.050 37.350 24.450 ;
        RECT 34.790 23.250 37.350 23.650 ;
        RECT 45.350 23.250 47.910 24.450 ;
        RECT 35.920 20.450 36.220 23.250 ;
        RECT 34.790 20.050 37.350 20.450 ;
        RECT 34.790 19.250 37.350 19.650 ;
        RECT 45.350 19.250 47.910 20.450 ;
        RECT 35.920 16.450 36.220 19.250 ;
        RECT 34.790 16.050 37.350 16.450 ;
        RECT 34.790 15.250 37.350 15.650 ;
        RECT 45.350 15.250 47.910 16.450 ;
        RECT 35.920 12.450 36.220 15.250 ;
        RECT 34.790 12.050 37.350 12.450 ;
        RECT 34.790 11.250 37.350 11.650 ;
        RECT 45.350 11.250 47.910 12.450 ;
        RECT 0.980 3.050 23.350 3.220 ;
        RECT 24.870 10.050 33.830 11.250 ;
        RECT 24.870 4.850 25.830 10.050 ;
        RECT 27.750 8.850 29.990 9.250 ;
        RECT 27.110 6.850 27.430 8.050 ;
        RECT 27.750 6.050 28.070 8.850 ;
        RECT 30.940 8.050 31.260 8.250 ;
        RECT 30.940 7.650 31.270 8.050 ;
        RECT 28.390 7.250 31.270 7.650 ;
        RECT 30.950 6.850 31.270 7.250 ;
        RECT 27.750 5.650 29.990 6.050 ;
        RECT 32.870 4.850 33.830 10.050 ;
        RECT 35.920 8.450 36.220 11.250 ;
        RECT 34.790 8.050 37.350 8.450 ;
        RECT 34.790 7.250 37.350 7.650 ;
        RECT 45.350 7.250 47.910 8.450 ;
        RECT 48.870 4.850 49.830 30.050 ;
        RECT 24.870 3.650 49.830 4.850 ;
        RECT 1.765 2.450 22.465 3.050 ;
        RECT 24.870 2.450 25.830 3.650 ;
        RECT 32.870 2.450 33.830 3.650 ;
        RECT 57.460 2.450 97.940 37.850 ;
        RECT 0.980 1.550 97.940 2.450 ;
        RECT 4.460 1.000 94.460 1.550 ;
        RECT 98.940 1.000 99.940 51.700 ;
        RECT 103.420 42.850 137.900 51.750 ;
        RECT 102.940 41.950 137.900 42.850 ;
        RECT 102.940 40.750 103.900 41.950 ;
        RECT 110.940 40.750 111.900 41.950 ;
        RECT 102.940 39.550 119.900 40.750 ;
        RECT 102.940 38.750 103.900 39.550 ;
        RECT 110.940 38.750 111.900 39.550 ;
        RECT 115.270 38.750 115.570 39.550 ;
        RECT 102.940 38.350 107.740 38.750 ;
        RECT 110.940 38.350 115.740 38.750 ;
        RECT 102.940 34.750 103.900 38.350 ;
        RECT 105.500 36.350 105.820 37.550 ;
        RECT 106.140 35.550 106.460 38.350 ;
        RECT 107.410 37.150 107.730 37.390 ;
        RECT 106.780 36.750 108.380 37.150 ;
        RECT 108.700 36.990 109.020 37.550 ;
        RECT 107.410 36.550 107.730 36.750 ;
        RECT 106.140 35.150 107.740 35.550 ;
        RECT 102.940 34.350 107.740 34.750 ;
        RECT 102.940 30.750 103.900 34.350 ;
        RECT 105.500 32.350 105.820 33.550 ;
        RECT 106.140 31.550 106.460 34.350 ;
        RECT 108.080 33.150 108.380 36.750 ;
        RECT 108.690 36.350 109.020 36.990 ;
        RECT 110.940 37.100 111.900 38.350 ;
        RECT 113.500 37.100 113.820 37.550 ;
        RECT 114.140 37.100 114.460 38.350 ;
        RECT 115.270 37.150 115.570 38.350 ;
        RECT 116.700 37.150 117.020 37.550 ;
        RECT 114.780 37.100 117.020 37.150 ;
        RECT 118.940 37.100 119.900 39.550 ;
        RECT 110.940 36.800 119.900 37.100 ;
        RECT 108.690 36.150 109.010 36.350 ;
        RECT 110.940 34.750 111.900 36.800 ;
        RECT 113.500 36.350 113.820 36.800 ;
        RECT 114.140 35.550 114.460 36.800 ;
        RECT 114.780 36.750 117.020 36.800 ;
        RECT 116.700 36.350 117.020 36.750 ;
        RECT 114.140 35.150 115.740 35.550 ;
        RECT 110.940 34.350 115.740 34.750 ;
        RECT 108.700 33.150 109.020 33.550 ;
        RECT 106.780 32.750 109.020 33.150 ;
        RECT 108.080 32.550 108.380 32.750 ;
        RECT 108.700 32.350 109.020 32.750 ;
        RECT 106.140 31.150 107.740 31.550 ;
        RECT 102.940 30.350 107.740 30.750 ;
        RECT 102.940 26.750 103.900 30.350 ;
        RECT 105.500 28.350 105.820 29.550 ;
        RECT 106.140 27.550 106.460 30.350 ;
        RECT 108.710 29.550 109.010 32.350 ;
        RECT 110.940 30.750 111.900 34.350 ;
        RECT 113.500 32.350 113.820 33.550 ;
        RECT 114.140 31.550 114.460 34.350 ;
        RECT 114.780 32.750 116.380 33.150 ;
        RECT 116.700 33.030 117.020 33.550 ;
        RECT 114.140 31.150 115.740 31.550 ;
        RECT 110.940 30.350 115.740 30.750 ;
        RECT 106.780 28.750 108.380 29.150 ;
        RECT 106.140 27.150 107.740 27.550 ;
        RECT 102.940 26.350 107.740 26.750 ;
        RECT 102.940 22.750 103.900 26.350 ;
        RECT 105.500 24.350 105.820 25.550 ;
        RECT 106.140 23.550 106.460 26.350 ;
        RECT 108.080 25.150 108.380 28.750 ;
        RECT 108.700 28.350 109.020 29.550 ;
        RECT 108.710 25.550 109.010 28.350 ;
        RECT 110.940 26.750 111.900 30.350 ;
        RECT 113.500 28.350 113.820 29.550 ;
        RECT 114.140 27.550 114.460 30.350 ;
        RECT 115.410 29.150 115.730 29.390 ;
        RECT 116.080 29.150 116.380 32.750 ;
        RECT 116.670 32.350 117.020 33.030 ;
        RECT 116.670 32.190 116.990 32.350 ;
        RECT 114.780 28.750 116.380 29.150 ;
        RECT 116.700 28.990 117.020 29.550 ;
        RECT 115.410 28.550 115.730 28.750 ;
        RECT 116.690 28.350 117.020 28.990 ;
        RECT 116.690 28.150 117.010 28.350 ;
        RECT 114.140 27.150 115.740 27.550 ;
        RECT 110.940 26.350 115.740 26.750 ;
        RECT 106.780 24.750 108.380 25.150 ;
        RECT 106.140 23.150 107.740 23.550 ;
        RECT 102.940 22.350 107.740 22.750 ;
        RECT 102.940 18.750 103.900 22.350 ;
        RECT 105.500 20.350 105.820 21.550 ;
        RECT 106.140 19.550 106.460 22.350 ;
        RECT 108.080 21.150 108.380 24.750 ;
        RECT 108.700 24.350 109.020 25.550 ;
        RECT 108.710 21.550 109.010 24.350 ;
        RECT 110.940 22.750 111.900 26.350 ;
        RECT 113.500 24.350 113.820 25.550 ;
        RECT 114.140 23.550 114.460 26.350 ;
        RECT 114.780 24.750 116.380 25.150 ;
        RECT 116.700 25.030 117.020 25.550 ;
        RECT 114.140 23.150 115.740 23.550 ;
        RECT 110.940 22.350 115.740 22.750 ;
        RECT 106.780 20.750 108.380 21.150 ;
        RECT 106.140 19.150 107.740 19.550 ;
        RECT 102.940 18.350 107.740 18.750 ;
        RECT 102.940 14.350 103.900 18.350 ;
        RECT 105.500 16.350 105.820 17.550 ;
        RECT 106.140 15.550 106.460 18.350 ;
        RECT 108.080 17.150 108.380 20.750 ;
        RECT 108.700 20.350 109.020 21.550 ;
        RECT 108.710 17.550 109.010 20.350 ;
        RECT 110.940 18.750 111.900 22.350 ;
        RECT 113.500 20.350 113.820 21.550 ;
        RECT 114.140 19.550 114.460 22.350 ;
        RECT 116.080 21.150 116.380 24.750 ;
        RECT 116.670 24.350 117.020 25.030 ;
        RECT 116.670 24.190 116.990 24.350 ;
        RECT 116.700 21.150 117.020 21.550 ;
        RECT 114.780 20.750 117.020 21.150 ;
        RECT 116.080 20.550 116.380 20.750 ;
        RECT 116.700 20.350 117.020 20.750 ;
        RECT 114.140 19.150 115.740 19.550 ;
        RECT 110.940 18.350 115.740 18.750 ;
        RECT 106.780 16.750 108.380 17.150 ;
        RECT 108.700 16.350 109.020 17.550 ;
        RECT 106.140 15.150 107.740 15.550 ;
        RECT 110.940 14.350 111.900 18.350 ;
        RECT 113.500 16.350 113.820 17.550 ;
        RECT 114.140 15.550 114.460 18.350 ;
        RECT 116.710 17.550 117.010 20.350 ;
        RECT 116.210 17.150 116.530 17.390 ;
        RECT 114.780 16.750 116.530 17.150 ;
        RECT 116.210 16.550 116.530 16.750 ;
        RECT 116.700 16.350 117.020 17.550 ;
        RECT 114.140 15.150 115.740 15.550 ;
        RECT 102.940 14.250 111.900 14.350 ;
        RECT 102.940 13.950 114.940 14.250 ;
        RECT 102.940 13.850 115.740 13.950 ;
        RECT 102.940 13.150 111.900 13.850 ;
        RECT 114.140 13.550 115.740 13.850 ;
        RECT 110.940 10.750 111.900 13.150 ;
        RECT 113.500 12.350 113.820 13.550 ;
        RECT 114.140 12.350 114.460 13.550 ;
        RECT 114.780 12.750 116.380 13.150 ;
        RECT 116.700 12.990 117.020 13.550 ;
        RECT 116.690 12.960 117.020 12.990 ;
        RECT 114.140 11.950 115.740 12.350 ;
        RECT 110.940 10.350 115.740 10.750 ;
        RECT 110.940 6.350 111.900 10.350 ;
        RECT 113.500 8.350 113.820 9.550 ;
        RECT 114.140 7.550 114.460 10.350 ;
        RECT 116.080 9.150 116.380 12.750 ;
        RECT 116.660 12.640 117.500 12.960 ;
        RECT 116.690 12.350 117.020 12.640 ;
        RECT 116.690 12.150 117.010 12.350 ;
        RECT 114.780 8.750 116.380 9.150 ;
        RECT 116.700 9.030 117.020 9.550 ;
        RECT 115.170 8.310 115.490 8.750 ;
        RECT 116.670 8.350 117.020 9.030 ;
        RECT 116.670 8.190 116.990 8.350 ;
        RECT 114.140 7.150 115.740 7.550 ;
        RECT 118.940 6.350 119.900 36.800 ;
        RECT 110.940 5.150 119.900 6.350 ;
        RECT 120.940 39.550 137.900 40.750 ;
        RECT 120.940 38.750 121.900 39.550 ;
        RECT 125.270 38.750 125.570 39.550 ;
        RECT 128.940 38.750 129.900 39.550 ;
        RECT 120.940 38.350 126.700 38.750 ;
        RECT 120.940 37.100 121.900 38.350 ;
        RECT 122.540 37.100 122.860 37.550 ;
        RECT 123.180 37.100 123.500 38.350 ;
        RECT 125.270 37.150 125.570 38.350 ;
        RECT 127.670 37.550 127.970 38.550 ;
        RECT 128.940 38.350 133.740 38.750 ;
        RECT 127.660 37.150 127.980 37.550 ;
        RECT 123.820 37.100 127.980 37.150 ;
        RECT 128.940 37.100 129.900 38.350 ;
        RECT 120.940 36.800 129.900 37.100 ;
        RECT 120.940 34.750 121.900 36.800 ;
        RECT 122.540 36.350 122.860 36.800 ;
        RECT 123.180 35.550 123.500 36.800 ;
        RECT 123.820 36.750 127.980 36.800 ;
        RECT 125.270 35.550 125.570 36.750 ;
        RECT 127.660 36.350 127.980 36.750 ;
        RECT 123.180 35.150 126.700 35.550 ;
        RECT 125.270 34.750 125.570 35.150 ;
        RECT 120.940 34.350 126.700 34.750 ;
        RECT 120.940 33.100 121.900 34.350 ;
        RECT 122.540 33.100 122.860 33.550 ;
        RECT 123.180 33.100 123.500 34.350 ;
        RECT 125.270 33.150 125.570 34.350 ;
        RECT 127.670 33.550 127.970 36.350 ;
        RECT 128.940 34.750 129.900 36.800 ;
        RECT 131.500 36.350 131.820 37.550 ;
        RECT 132.140 35.550 132.460 38.350 ;
        RECT 132.780 36.750 134.380 37.150 ;
        RECT 134.700 36.990 135.020 37.550 ;
        RECT 132.140 35.150 133.740 35.550 ;
        RECT 128.940 34.350 133.740 34.750 ;
        RECT 127.660 33.150 127.980 33.550 ;
        RECT 123.820 33.100 127.980 33.150 ;
        RECT 128.940 33.100 129.900 34.350 ;
        RECT 120.940 32.800 129.900 33.100 ;
        RECT 120.940 30.750 121.900 32.800 ;
        RECT 122.540 32.350 122.860 32.800 ;
        RECT 123.180 31.550 123.500 32.800 ;
        RECT 123.820 32.750 127.980 32.800 ;
        RECT 125.270 31.550 125.570 32.750 ;
        RECT 127.660 32.350 127.980 32.750 ;
        RECT 123.180 31.150 126.700 31.550 ;
        RECT 125.270 30.750 125.570 31.150 ;
        RECT 120.940 30.350 126.700 30.750 ;
        RECT 120.940 29.100 121.900 30.350 ;
        RECT 122.540 29.100 122.860 29.550 ;
        RECT 123.180 29.100 123.500 30.350 ;
        RECT 125.270 29.150 125.570 30.350 ;
        RECT 127.670 29.550 127.970 32.350 ;
        RECT 128.940 30.750 129.900 32.800 ;
        RECT 131.500 32.350 131.820 33.550 ;
        RECT 132.140 31.550 132.460 34.350 ;
        RECT 134.080 33.150 134.380 36.750 ;
        RECT 134.690 36.350 135.020 36.990 ;
        RECT 134.690 36.150 135.010 36.350 ;
        RECT 134.700 33.150 135.020 33.550 ;
        RECT 132.780 32.750 135.020 33.150 ;
        RECT 134.080 32.550 134.380 32.750 ;
        RECT 134.700 32.350 135.020 32.750 ;
        RECT 132.140 31.150 133.740 31.550 ;
        RECT 128.940 30.350 133.740 30.750 ;
        RECT 127.660 29.150 127.980 29.550 ;
        RECT 123.820 29.100 127.980 29.150 ;
        RECT 128.940 29.100 129.900 30.350 ;
        RECT 120.940 28.800 129.900 29.100 ;
        RECT 120.940 26.750 121.900 28.800 ;
        RECT 122.540 28.350 122.860 28.800 ;
        RECT 123.180 27.550 123.500 28.800 ;
        RECT 123.820 28.750 127.980 28.800 ;
        RECT 125.270 27.550 125.570 28.750 ;
        RECT 127.660 28.350 127.980 28.750 ;
        RECT 123.180 27.150 126.700 27.550 ;
        RECT 125.270 26.750 125.570 27.150 ;
        RECT 120.940 26.350 126.700 26.750 ;
        RECT 120.940 25.100 121.900 26.350 ;
        RECT 122.540 25.100 122.860 25.550 ;
        RECT 123.180 25.100 123.500 26.350 ;
        RECT 125.270 25.150 125.570 26.350 ;
        RECT 127.670 25.550 127.970 28.350 ;
        RECT 128.940 26.750 129.900 28.800 ;
        RECT 131.500 28.350 131.820 29.550 ;
        RECT 132.140 27.550 132.460 30.350 ;
        RECT 134.710 29.550 135.010 32.350 ;
        RECT 132.780 28.750 134.380 29.150 ;
        RECT 132.140 27.150 133.740 27.550 ;
        RECT 128.940 26.350 133.740 26.750 ;
        RECT 127.660 25.150 127.980 25.550 ;
        RECT 123.820 25.100 127.980 25.150 ;
        RECT 128.940 25.100 129.900 26.350 ;
        RECT 120.940 24.800 129.900 25.100 ;
        RECT 120.940 14.350 121.900 24.800 ;
        RECT 122.540 24.350 122.860 24.800 ;
        RECT 123.180 23.550 123.500 24.800 ;
        RECT 123.820 24.750 127.980 24.800 ;
        RECT 127.660 24.350 127.980 24.750 ;
        RECT 123.180 23.150 126.700 23.550 ;
        RECT 128.940 22.750 129.900 24.800 ;
        RECT 131.500 24.350 131.820 25.550 ;
        RECT 132.140 23.550 132.460 26.350 ;
        RECT 134.080 25.150 134.380 28.750 ;
        RECT 134.700 28.350 135.020 29.550 ;
        RECT 134.710 25.550 135.010 28.350 ;
        RECT 132.780 24.750 134.380 25.150 ;
        RECT 132.140 23.150 133.740 23.550 ;
        RECT 123.180 22.350 126.700 22.750 ;
        RECT 128.940 22.350 133.740 22.750 ;
        RECT 122.540 20.350 122.860 21.550 ;
        RECT 123.180 19.550 123.500 22.350 ;
        RECT 123.820 20.750 127.340 21.150 ;
        RECT 127.660 20.990 127.980 21.550 ;
        RECT 127.650 20.350 127.980 20.990 ;
        RECT 127.650 20.150 127.970 20.350 ;
        RECT 123.180 19.150 126.700 19.550 ;
        RECT 123.180 18.750 123.480 19.150 ;
        RECT 128.940 18.750 129.900 22.350 ;
        RECT 131.500 20.350 131.820 21.550 ;
        RECT 132.140 19.550 132.460 22.350 ;
        RECT 134.080 21.150 134.380 24.750 ;
        RECT 134.700 24.350 135.020 25.550 ;
        RECT 134.710 21.550 135.010 24.350 ;
        RECT 132.780 20.750 134.380 21.150 ;
        RECT 134.700 20.350 135.020 21.550 ;
        RECT 132.140 19.150 133.740 19.550 ;
        RECT 123.180 18.350 126.700 18.750 ;
        RECT 128.940 18.350 133.740 18.750 ;
        RECT 122.540 16.350 122.860 17.550 ;
        RECT 123.180 15.550 123.500 18.350 ;
        RECT 123.820 16.750 127.340 17.150 ;
        RECT 127.660 16.990 127.980 17.550 ;
        RECT 127.650 16.350 127.980 16.990 ;
        RECT 127.650 16.150 127.970 16.350 ;
        RECT 123.180 15.150 126.700 15.550 ;
        RECT 128.940 14.350 129.900 18.350 ;
        RECT 131.500 16.350 131.820 17.550 ;
        RECT 132.140 15.550 132.460 18.350 ;
        RECT 134.710 17.550 135.010 20.350 ;
        RECT 132.780 16.750 134.380 17.150 ;
        RECT 134.700 16.350 135.020 17.550 ;
        RECT 132.140 15.150 133.740 15.550 ;
        RECT 136.940 14.350 137.900 39.550 ;
        RECT 159.015 30.565 160.485 30.735 ;
        RECT 159.015 29.435 159.185 30.565 ;
        RECT 159.505 29.835 159.995 30.165 ;
        RECT 160.315 29.435 160.485 30.565 ;
        RECT 159.015 29.265 160.485 29.435 ;
        RECT 120.940 13.150 137.900 14.350 ;
        RECT 120.940 3.950 121.900 13.150 ;
        RECT 128.940 3.950 129.900 13.150 ;
        RECT 144.490 7.300 145.390 21.750 ;
        RECT 148.090 21.000 151.690 21.300 ;
        RECT 148.100 20.980 148.940 21.000 ;
        RECT 146.290 20.600 147.190 20.900 ;
        RECT 152.590 20.600 153.490 20.900 ;
        RECT 146.890 20.300 147.790 20.600 ;
        RECT 146.290 19.800 147.190 20.100 ;
        RECT 147.490 20.000 147.790 20.300 ;
        RECT 148.090 20.500 148.930 20.520 ;
        RECT 150.790 20.500 151.630 20.520 ;
        RECT 148.090 20.200 148.990 20.500 ;
        RECT 150.790 20.200 151.690 20.500 ;
        RECT 146.590 19.430 146.890 19.800 ;
        RECT 147.490 19.700 148.390 20.000 ;
        RECT 152.590 19.800 153.490 20.100 ;
        RECT 146.260 19.110 147.100 19.430 ;
        RECT 148.090 19.400 151.690 19.700 ;
        RECT 148.090 18.600 151.690 18.900 ;
        RECT 148.100 18.580 148.940 18.600 ;
        RECT 146.290 18.200 147.190 18.500 ;
        RECT 152.590 18.200 153.490 18.500 ;
        RECT 146.890 17.900 147.790 18.200 ;
        RECT 146.290 17.400 147.190 17.700 ;
        RECT 147.490 17.600 147.790 17.900 ;
        RECT 148.090 18.100 148.930 18.120 ;
        RECT 150.790 18.100 151.630 18.120 ;
        RECT 148.090 17.800 148.990 18.100 ;
        RECT 150.790 17.800 151.690 18.100 ;
        RECT 146.300 17.380 147.140 17.400 ;
        RECT 147.490 17.300 148.390 17.600 ;
        RECT 152.590 17.400 153.490 17.700 ;
        RECT 148.090 17.000 151.690 17.300 ;
        RECT 146.260 16.310 147.100 16.630 ;
        RECT 148.090 16.500 148.930 16.520 ;
        RECT 146.590 16.100 146.890 16.310 ;
        RECT 148.090 16.200 148.990 16.500 ;
        RECT 149.290 16.200 151.690 16.500 ;
        RECT 146.290 15.800 147.190 16.100 ;
        RECT 149.290 15.700 149.590 16.200 ;
        RECT 152.590 15.800 153.490 16.100 ;
        RECT 148.090 15.400 149.590 15.700 ;
        RECT 150.790 15.400 151.690 15.700 ;
        RECT 148.100 15.380 148.940 15.400 ;
        RECT 146.290 15.000 147.190 15.300 ;
        RECT 152.590 15.000 153.490 15.300 ;
        RECT 146.590 14.630 146.890 15.000 ;
        RECT 148.090 14.900 148.930 14.920 ;
        RECT 150.790 14.900 151.630 14.920 ;
        RECT 146.260 14.310 147.100 14.630 ;
        RECT 148.090 14.600 148.990 14.900 ;
        RECT 150.790 14.600 151.690 14.900 ;
        RECT 148.090 14.100 148.930 14.120 ;
        RECT 148.090 13.800 148.990 14.100 ;
        RECT 149.290 13.800 151.690 14.100 ;
        RECT 146.290 13.630 147.190 13.700 ;
        RECT 146.260 13.400 147.190 13.630 ;
        RECT 146.260 13.310 147.100 13.400 ;
        RECT 149.290 13.300 149.590 13.800 ;
        RECT 152.590 13.400 153.490 13.700 ;
        RECT 148.090 13.000 149.590 13.300 ;
        RECT 150.790 13.000 151.690 13.300 ;
        RECT 148.100 12.980 148.940 13.000 ;
        RECT 146.290 12.600 147.190 12.900 ;
        RECT 152.590 12.600 153.490 12.900 ;
        RECT 146.590 12.230 146.890 12.600 ;
        RECT 148.090 12.500 148.930 12.520 ;
        RECT 150.790 12.500 151.630 12.520 ;
        RECT 146.260 11.910 147.100 12.230 ;
        RECT 148.090 12.200 148.990 12.500 ;
        RECT 150.790 12.200 151.690 12.500 ;
        RECT 148.090 11.400 151.690 11.700 ;
        RECT 148.100 11.380 148.940 11.400 ;
        RECT 146.290 11.000 147.790 11.300 ;
        RECT 152.590 11.000 153.490 11.300 ;
        RECT 146.290 9.630 147.190 9.700 ;
        RECT 146.260 9.400 147.190 9.630 ;
        RECT 146.260 9.310 147.100 9.400 ;
        RECT 147.490 9.300 147.790 11.000 ;
        RECT 148.090 10.900 148.930 10.920 ;
        RECT 150.790 10.900 151.630 10.920 ;
        RECT 148.090 10.600 148.990 10.900 ;
        RECT 150.790 10.600 151.690 10.900 ;
        RECT 148.090 10.100 148.930 10.120 ;
        RECT 148.090 9.800 148.990 10.100 ;
        RECT 149.290 9.800 151.690 10.100 ;
        RECT 149.290 9.300 149.590 9.800 ;
        RECT 152.590 9.400 153.490 9.700 ;
        RECT 147.490 9.000 149.590 9.300 ;
        RECT 150.790 9.000 151.690 9.300 ;
        RECT 146.290 8.600 147.190 8.900 ;
        RECT 152.590 8.600 153.490 8.900 ;
        RECT 146.300 8.580 147.140 8.600 ;
        RECT 148.090 8.500 148.930 8.520 ;
        RECT 150.790 8.500 151.630 8.520 ;
        RECT 148.090 8.200 148.990 8.500 ;
        RECT 150.790 8.200 151.690 8.500 ;
        RECT 148.090 7.700 148.930 7.720 ;
        RECT 150.790 7.700 151.630 7.720 ;
        RECT 147.490 7.400 148.990 7.700 ;
        RECT 150.790 7.400 152.290 7.700 ;
        RECT 147.490 7.300 147.790 7.400 ;
        RECT 144.490 7.000 147.790 7.300 ;
        RECT 141.105 6.765 142.575 6.935 ;
        RECT 141.105 5.635 141.275 6.765 ;
        RECT 141.595 6.035 142.085 6.365 ;
        RECT 142.405 5.635 142.575 6.765 ;
        RECT 141.105 5.465 142.575 5.635 ;
        RECT 103.420 2.450 137.900 3.950 ;
        RECT 139.905 3.765 141.375 3.935 ;
        RECT 139.905 2.635 140.075 3.765 ;
        RECT 140.395 3.035 140.885 3.365 ;
        RECT 141.205 2.635 141.375 3.765 ;
        RECT 139.905 2.465 141.375 2.635 ;
        RECT 102.940 1.550 137.940 2.450 ;
        RECT 4.460 0.950 99.940 1.000 ;
        RECT 140.490 0.950 140.790 2.465 ;
        RECT 141.690 0.950 141.990 5.465 ;
        RECT 144.490 2.500 145.390 7.000 ;
        RECT 147.490 6.900 147.790 7.000 ;
        RECT 151.990 7.300 152.290 7.400 ;
        RECT 154.390 7.300 155.290 21.750 ;
        RECT 151.990 7.000 155.290 7.300 ;
        RECT 148.090 6.900 148.930 6.920 ;
        RECT 150.790 6.900 151.630 6.920 ;
        RECT 151.990 6.900 152.290 7.000 ;
        RECT 147.490 6.600 148.990 6.900 ;
        RECT 150.790 6.600 152.290 6.900 ;
        RECT 148.090 5.800 151.690 6.100 ;
        RECT 148.100 5.780 148.940 5.800 ;
        RECT 146.290 5.630 147.190 5.700 ;
        RECT 146.260 5.400 147.190 5.630 ;
        RECT 152.590 5.400 153.490 5.700 ;
        RECT 146.260 5.310 147.100 5.400 ;
        RECT 148.090 5.300 148.930 5.320 ;
        RECT 150.790 5.300 151.630 5.320 ;
        RECT 148.090 5.000 148.990 5.300 ;
        RECT 150.790 5.000 151.690 5.300 ;
        RECT 148.090 4.200 151.690 4.500 ;
        RECT 148.100 4.180 148.940 4.200 ;
        RECT 146.290 3.800 147.190 4.100 ;
        RECT 152.590 3.800 153.490 4.100 ;
        RECT 146.590 3.500 146.890 3.800 ;
        RECT 148.090 3.700 148.930 3.720 ;
        RECT 150.790 3.700 151.630 3.720 ;
        RECT 146.300 3.180 147.140 3.500 ;
        RECT 148.090 3.400 148.990 3.700 ;
        RECT 150.790 3.400 151.690 3.700 ;
        RECT 148.090 2.900 148.930 2.920 ;
        RECT 150.790 2.900 151.630 2.920 ;
        RECT 147.490 2.600 148.990 2.900 ;
        RECT 150.790 2.600 152.290 2.900 ;
        RECT 147.490 2.500 147.790 2.600 ;
        RECT 144.490 2.200 147.790 2.500 ;
        RECT 144.490 1.350 145.390 2.200 ;
        RECT 147.490 2.100 147.790 2.200 ;
        RECT 151.990 2.500 152.290 2.600 ;
        RECT 154.390 2.500 155.290 7.000 ;
        RECT 151.990 2.200 155.290 2.500 ;
        RECT 148.090 2.100 148.930 2.120 ;
        RECT 150.790 2.100 151.630 2.120 ;
        RECT 151.990 2.100 152.290 2.200 ;
        RECT 147.490 1.800 148.990 2.100 ;
        RECT 150.790 1.800 152.290 2.100 ;
        RECT 154.390 1.350 155.290 2.200 ;
        RECT 0.500 0.050 155.020 0.950 ;
        RECT 77.260 0.000 99.940 0.050 ;
      LAYER met1 ;
        RECT 0.500 108.610 155.020 109.510 ;
        RECT 36.500 107.050 37.380 107.930 ;
        RECT 44.500 107.050 45.380 107.930 ;
        RECT 52.500 107.050 53.380 107.930 ;
        RECT 112.860 105.750 113.200 106.150 ;
        RECT 112.860 105.350 113.260 105.750 ;
        RECT 119.930 105.610 120.270 106.490 ;
        RECT 119.940 105.350 120.260 105.610 ;
        RECT 112.860 105.270 113.250 105.350 ;
        RECT 80.300 100.750 80.700 101.150 ;
        RECT 79.140 100.380 80.020 100.720 ;
        RECT 75.540 96.350 76.420 96.690 ;
        RECT 6.570 90.450 6.910 91.330 ;
        RECT 14.570 90.450 14.910 91.330 ;
        RECT 6.590 87.330 6.890 90.450 ;
        RECT 14.590 87.330 14.890 90.450 ;
        RECT 21.020 90.390 21.900 90.420 ;
        RECT 20.980 90.080 21.900 90.390 ;
        RECT 20.980 90.050 21.860 90.080 ;
        RECT 6.570 86.450 6.910 87.330 ;
        RECT 14.570 86.450 14.910 87.330 ;
        RECT 6.590 83.330 6.890 86.450 ;
        RECT 14.590 83.330 14.890 86.450 ;
        RECT 6.570 82.450 6.910 83.330 ;
        RECT 14.570 82.450 14.910 83.330 ;
        RECT 6.590 79.330 6.890 82.450 ;
        RECT 14.590 79.330 14.890 82.450 ;
        RECT 6.570 78.450 6.910 79.330 ;
        RECT 14.570 78.450 14.910 79.330 ;
        RECT 6.590 75.330 6.890 78.450 ;
        RECT 14.590 75.330 14.890 78.450 ;
        RECT 6.570 74.450 6.910 75.330 ;
        RECT 14.570 74.450 14.910 75.330 ;
        RECT 6.590 71.330 6.890 74.450 ;
        RECT 14.590 71.330 14.890 74.450 ;
        RECT 6.570 70.450 6.910 71.330 ;
        RECT 14.570 70.450 14.910 71.330 ;
        RECT 6.590 67.330 6.890 70.450 ;
        RECT 14.590 67.330 14.890 70.450 ;
        RECT 6.570 66.450 6.910 67.330 ;
        RECT 14.570 66.450 14.910 67.330 ;
        RECT 6.590 63.330 6.890 66.450 ;
        RECT 14.590 63.330 14.890 66.450 ;
        RECT 6.570 62.450 6.910 63.330 ;
        RECT 14.570 62.450 14.910 63.330 ;
        RECT 4.020 62.050 4.900 62.390 ;
        RECT 6.590 59.330 6.890 62.450 ;
        RECT 12.660 62.050 13.540 62.390 ;
        RECT 11.380 61.250 12.260 61.590 ;
        RECT 14.590 59.330 14.890 62.450 ;
        RECT 6.570 58.450 6.910 59.330 ;
        RECT 14.570 58.450 14.910 59.330 ;
        RECT 4.020 58.050 4.900 58.390 ;
        RECT 6.590 55.330 6.890 58.450 ;
        RECT 12.660 58.070 13.540 58.410 ;
        RECT 11.380 57.250 12.260 57.590 ;
        RECT 14.590 55.330 14.890 58.450 ;
        RECT 6.570 54.450 6.910 55.330 ;
        RECT 14.570 54.450 14.910 55.330 ;
        RECT 4.020 54.050 4.900 54.390 ;
        RECT 6.590 51.330 6.890 54.450 ;
        RECT 12.660 54.070 13.540 54.410 ;
        RECT 11.380 53.250 12.260 53.590 ;
        RECT 14.590 51.330 14.890 54.450 ;
        RECT 6.570 50.450 6.910 51.330 ;
        RECT 14.570 50.450 14.910 51.330 ;
        RECT 4.020 50.050 4.900 50.390 ;
        RECT 6.590 47.330 6.890 50.450 ;
        RECT 12.660 50.070 13.540 50.410 ;
        RECT 11.380 49.250 12.260 49.590 ;
        RECT 14.590 47.330 14.890 50.450 ;
        RECT 6.570 46.450 6.910 47.330 ;
        RECT 14.570 46.450 14.910 47.330 ;
        RECT 4.020 46.050 4.900 46.390 ;
        RECT 6.590 43.330 6.890 46.450 ;
        RECT 12.660 46.070 13.540 46.410 ;
        RECT 11.380 45.250 12.260 45.590 ;
        RECT 14.590 43.330 14.890 46.450 ;
        RECT 6.570 42.450 6.910 43.330 ;
        RECT 14.570 42.450 14.910 43.330 ;
        RECT 4.020 42.050 4.900 42.390 ;
        RECT 6.590 34.720 6.890 42.450 ;
        RECT 12.700 42.080 13.580 42.420 ;
        RECT 11.380 41.250 12.260 41.590 ;
        RECT 6.300 34.380 7.180 34.720 ;
        RECT 12.990 32.920 13.290 42.080 ;
        RECT 14.590 34.120 14.890 42.450 ;
        RECT 14.300 33.780 15.180 34.120 ;
        RECT 21.310 33.520 21.610 90.050 ;
        RECT 63.140 88.380 64.020 88.720 ;
        RECT 71.140 88.380 72.020 88.720 ;
        RECT 59.540 84.380 60.420 84.720 ;
        RECT 59.540 71.020 59.840 84.380 ;
        RECT 60.660 82.760 61.540 83.100 ;
        RECT 62.730 73.030 63.130 73.430 ;
        RECT 60.210 71.880 61.090 72.220 ;
        RECT 59.250 70.680 60.130 71.020 ;
        RECT 60.500 63.920 60.800 71.880 ;
        RECT 63.720 69.220 64.020 88.380 ;
        RECT 64.490 84.750 64.830 85.630 ;
        RECT 62.780 68.880 64.310 69.220 ;
        RECT 63.070 64.590 63.370 68.880 ;
        RECT 60.500 63.580 61.380 63.920 ;
        RECT 63.050 63.710 63.390 64.590 ;
        RECT 63.060 43.670 63.400 44.550 ;
        RECT 64.510 38.250 64.810 84.750 ;
        RECT 67.540 84.380 68.420 84.720 ;
        RECT 67.540 71.020 67.840 84.380 ;
        RECT 68.660 82.760 69.540 83.100 ;
        RECT 71.720 71.620 72.020 88.380 ;
        RECT 72.490 84.750 72.830 85.630 ;
        RECT 70.790 71.280 72.310 71.620 ;
        RECT 67.250 70.680 68.130 71.020 ;
        RECT 69.180 69.480 70.060 69.820 ;
        RECT 69.470 63.920 69.770 69.480 ;
        RECT 71.080 64.590 71.380 71.280 ;
        RECT 69.180 63.580 70.060 63.920 ;
        RECT 71.040 63.710 71.380 64.590 ;
        RECT 71.060 43.670 71.400 44.550 ;
        RECT 72.510 38.250 72.810 84.750 ;
        RECT 75.540 84.360 76.420 84.700 ;
        RECT 77.340 80.380 78.220 80.720 ;
        RECT 76.210 71.280 77.090 71.620 ;
        RECT 76.500 63.920 76.800 71.280 ;
        RECT 77.630 68.620 77.930 80.380 ;
        RECT 79.720 71.620 80.020 100.380 ;
        RECT 80.350 97.150 80.650 100.750 ;
        RECT 101.360 99.840 102.240 100.180 ;
        RECT 80.300 96.750 80.700 97.150 ;
        RECT 80.350 89.150 80.650 96.750 ;
        RECT 80.300 89.110 80.700 89.150 ;
        RECT 80.260 88.750 80.700 89.110 ;
        RECT 80.260 88.710 80.660 88.750 ;
        RECT 80.340 84.750 80.680 85.630 ;
        RECT 80.320 80.510 80.660 81.390 ;
        RECT 87.050 80.510 87.390 81.390 ;
        RECT 80.360 73.420 80.660 80.510 ;
        RECT 80.330 73.080 81.210 73.420 ;
        RECT 87.070 71.620 87.370 80.510 ;
        RECT 101.690 72.890 101.990 99.840 ;
        RECT 112.950 98.790 113.250 105.270 ;
        RECT 115.140 99.980 116.020 100.320 ;
        RECT 115.430 99.030 115.730 99.980 ;
        RECT 115.170 98.790 115.730 99.030 ;
        RECT 112.930 97.910 113.270 98.790 ;
        RECT 115.170 98.520 115.750 98.790 ;
        RECT 115.140 98.180 116.020 98.520 ;
        RECT 116.670 98.270 117.010 99.150 ;
        RECT 115.170 98.150 115.750 98.180 ;
        RECT 115.410 97.910 115.750 98.150 ;
        RECT 116.690 94.680 117.030 95.190 ;
        RECT 116.660 94.340 117.540 94.680 ;
        RECT 116.690 94.310 117.030 94.340 ;
        RECT 116.210 90.520 116.550 90.790 ;
        RECT 116.710 90.520 117.010 94.310 ;
        RECT 116.210 90.180 117.300 90.520 ;
        RECT 116.210 89.910 116.550 90.180 ;
        RECT 111.340 88.510 111.680 89.390 ;
        RECT 107.140 78.180 108.020 78.520 ;
        RECT 107.430 73.920 107.730 78.180 ;
        RECT 108.690 74.310 109.030 75.190 ;
        RECT 107.140 73.580 108.020 73.920 ;
        RECT 101.400 72.550 102.280 72.890 ;
        RECT 79.430 71.280 80.310 71.620 ;
        RECT 81.495 71.280 82.375 71.620 ;
        RECT 86.780 71.280 87.660 71.620 ;
        RECT 78.790 70.680 79.670 71.020 ;
        RECT 77.340 68.280 78.220 68.620 ;
        RECT 79.080 64.590 79.380 70.680 ;
        RECT 76.500 63.580 77.380 63.920 ;
        RECT 79.040 63.710 79.380 64.590 ;
        RECT 79.060 47.670 79.400 48.550 ;
        RECT 36.500 37.910 37.380 38.250 ;
        RECT 44.500 37.910 45.380 38.250 ;
        RECT 52.500 37.910 53.380 38.250 ;
        RECT 64.510 38.050 64.960 38.250 ;
        RECT 72.510 38.050 72.960 38.250 ;
        RECT 36.830 34.720 37.130 37.910 ;
        RECT 44.830 34.720 45.130 37.910 ;
        RECT 36.540 34.380 37.420 34.720 ;
        RECT 44.540 34.380 45.420 34.720 ;
        RECT 52.830 34.120 53.130 37.910 ;
        RECT 64.640 37.850 64.960 38.050 ;
        RECT 72.640 37.850 72.960 38.050 ;
        RECT 52.540 33.780 53.420 34.120 ;
        RECT 64.650 33.520 64.950 37.850 ;
        RECT 21.020 33.180 21.900 33.520 ;
        RECT 64.360 33.180 65.240 33.520 ;
        RECT 72.650 32.920 72.950 37.850 ;
        RECT 81.785 34.120 82.085 71.280 ;
        RECT 108.710 71.190 109.010 74.310 ;
        RECT 107.410 69.910 107.750 70.790 ;
        RECT 108.690 70.310 109.030 71.190 ;
        RECT 109.670 70.310 110.010 71.190 ;
        RECT 82.610 68.280 83.490 68.620 ;
        RECT 82.900 48.720 83.200 68.280 ;
        RECT 105.160 54.650 106.040 55.530 ;
        RECT 105.160 51.770 106.040 52.650 ;
        RECT 82.900 48.380 83.780 48.720 ;
        RECT 82.900 43.560 83.780 43.900 ;
        RECT 107.410 36.510 107.750 37.390 ;
        RECT 109.690 36.990 109.990 70.310 ;
        RECT 111.360 37.560 111.660 88.510 ;
        RECT 115.460 86.180 116.340 86.520 ;
        RECT 116.670 82.270 117.010 83.150 ;
        RECT 119.950 79.190 120.250 105.350 ;
        RECT 121.100 105.130 121.980 105.470 ;
        RECT 115.410 77.910 115.750 78.790 ;
        RECT 116.690 78.310 117.030 79.190 ;
        RECT 119.930 78.310 120.270 79.190 ;
        RECT 116.670 74.270 117.010 75.150 ;
        RECT 108.690 36.110 109.030 36.990 ;
        RECT 109.670 36.110 110.010 36.990 ;
        RECT 111.340 36.680 111.680 37.560 ;
        RECT 81.495 33.780 82.375 34.120 ;
        RECT 107.140 33.380 108.020 33.720 ;
        RECT 12.700 32.580 13.580 32.920 ;
        RECT 30.670 32.580 31.550 32.920 ;
        RECT 72.360 32.580 73.240 32.920 ;
        RECT 20.575 31.980 21.455 32.320 ;
        RECT 28.430 31.980 29.310 32.320 ;
        RECT 20.865 23.235 21.165 31.980 ;
        RECT 3.165 19.235 21.165 23.235 ;
        RECT 3.165 8.735 7.165 19.235 ;
        RECT 10.165 12.235 14.165 16.235 ;
        RECT 17.165 8.735 21.165 19.235 ;
        RECT 3.165 5.235 21.165 8.735 ;
        RECT 28.720 6.020 29.020 31.980 ;
        RECT 30.960 8.290 31.260 32.580 ;
        RECT 34.500 31.980 35.380 32.320 ;
        RECT 30.940 7.410 31.280 8.290 ;
        RECT 34.790 7.620 35.090 31.980 ;
        RECT 107.430 29.120 107.730 33.380 ;
        RECT 108.710 32.990 109.010 36.110 ;
        RECT 108.690 32.110 109.030 32.990 ;
        RECT 116.670 32.150 117.010 33.030 ;
        RECT 107.140 28.780 108.020 29.120 ;
        RECT 115.410 28.510 115.750 29.390 ;
        RECT 36.390 28.060 37.270 28.400 ;
        RECT 116.690 28.110 117.030 28.990 ;
        RECT 119.930 28.110 120.270 28.990 ;
        RECT 116.670 24.150 117.010 25.030 ;
        RECT 115.460 20.780 116.340 21.120 ;
        RECT 116.210 17.120 116.550 17.390 ;
        RECT 116.210 16.780 117.300 17.120 ;
        RECT 116.210 16.510 116.550 16.780 ;
        RECT 116.710 12.990 117.010 16.780 ;
        RECT 116.690 12.960 117.030 12.990 ;
        RECT 116.660 12.620 117.540 12.960 ;
        RECT 116.690 12.110 117.030 12.620 ;
        RECT 112.930 8.510 113.270 9.390 ;
        RECT 115.410 9.150 115.750 9.390 ;
        RECT 115.170 9.120 115.750 9.150 ;
        RECT 115.140 8.780 116.020 9.120 ;
        RECT 115.170 8.510 115.750 8.780 ;
        RECT 34.790 7.280 35.670 7.620 ;
        RECT 28.430 5.680 29.310 6.020 ;
        RECT 112.950 2.350 113.250 8.510 ;
        RECT 115.170 8.270 115.730 8.510 ;
        RECT 115.430 7.320 115.730 8.270 ;
        RECT 116.670 8.150 117.010 9.030 ;
        RECT 115.140 6.980 116.020 7.320 ;
        RECT 112.910 1.950 113.250 2.350 ;
        RECT 119.950 2.190 120.250 28.110 ;
        RECT 112.910 1.550 113.260 1.950 ;
        RECT 112.910 1.470 113.250 1.550 ;
        RECT 119.930 1.310 120.270 2.190 ;
        RECT 121.390 2.170 121.690 105.130 ;
        RECT 133.140 99.980 134.020 100.320 ;
        RECT 125.140 90.180 126.020 90.520 ;
        RECT 127.650 90.310 127.990 91.190 ;
        RECT 133.430 90.520 133.730 99.980 ;
        RECT 133.140 90.180 134.020 90.520 ;
        RECT 125.140 86.180 126.020 86.520 ;
        RECT 127.650 86.310 127.990 87.190 ;
        RECT 129.330 86.310 129.670 87.190 ;
        RECT 124.500 84.580 125.380 84.920 ;
        RECT 124.790 78.520 125.090 84.580 ;
        RECT 124.500 78.180 125.380 78.520 ;
        RECT 129.350 55.050 129.650 86.310 ;
        RECT 133.140 78.180 134.020 78.520 ;
        RECT 133.460 74.180 134.340 74.520 ;
        RECT 133.750 73.920 134.050 74.180 ;
        RECT 133.460 73.580 134.340 73.920 ;
        RECT 134.690 70.310 135.030 71.190 ;
        RECT 136.070 70.310 136.410 71.190 ;
        RECT 129.340 54.650 129.660 55.050 ;
        RECT 129.350 52.890 129.650 54.650 ;
        RECT 129.330 52.010 129.670 52.890 ;
        RECT 124.500 28.780 125.380 29.120 ;
        RECT 124.790 22.720 125.090 28.780 ;
        RECT 124.500 22.380 125.380 22.720 ;
        RECT 125.140 20.780 126.020 21.120 ;
        RECT 129.350 20.990 129.650 52.010 ;
        RECT 136.090 36.990 136.390 70.310 ;
        RECT 134.690 36.110 135.030 36.990 ;
        RECT 136.070 36.110 136.410 36.990 ;
        RECT 133.460 33.380 134.340 33.720 ;
        RECT 133.750 33.120 134.050 33.380 ;
        RECT 133.460 32.780 134.340 33.120 ;
        RECT 159.475 29.725 160.025 30.275 ;
        RECT 133.140 28.780 134.020 29.120 ;
        RECT 148.370 21.320 148.710 21.590 ;
        RECT 127.650 20.110 127.990 20.990 ;
        RECT 129.330 20.110 129.670 20.990 ;
        RECT 148.100 20.980 148.980 21.320 ;
        RECT 148.370 20.710 148.710 20.980 ;
        RECT 148.090 20.200 148.970 20.540 ;
        RECT 150.790 20.200 151.670 20.540 ;
        RECT 154.090 19.450 154.390 19.500 ;
        RECT 146.260 19.110 147.140 19.450 ;
        RECT 153.760 19.110 154.640 19.450 ;
        RECT 148.100 18.580 148.980 18.920 ;
        RECT 152.600 18.580 153.480 18.920 ;
        RECT 148.090 17.800 148.970 18.140 ;
        RECT 150.790 17.800 151.670 18.140 ;
        RECT 146.300 17.650 147.180 17.720 ;
        RECT 146.260 17.380 147.180 17.650 ;
        RECT 146.260 17.310 147.140 17.380 ;
        RECT 125.140 16.780 126.020 17.120 ;
        RECT 127.650 16.110 127.990 16.990 ;
        RECT 133.140 16.780 134.020 17.120 ;
        RECT 133.430 7.320 133.730 16.780 ;
        RECT 152.890 16.650 153.190 18.580 ;
        RECT 146.260 16.310 147.140 16.650 ;
        RECT 148.090 16.200 148.970 16.540 ;
        RECT 152.560 16.310 153.440 16.650 ;
        RECT 144.800 15.380 145.680 15.720 ;
        RECT 148.100 15.380 148.980 15.720 ;
        RECT 145.090 13.650 145.390 15.380 ;
        RECT 146.260 14.310 147.140 14.650 ;
        RECT 148.090 14.600 148.970 14.940 ;
        RECT 150.790 14.600 151.670 14.940 ;
        RECT 154.090 14.650 154.390 19.110 ;
        RECT 153.760 14.310 154.640 14.650 ;
        RECT 148.090 13.800 148.970 14.140 ;
        RECT 144.760 13.310 145.640 13.650 ;
        RECT 146.260 13.310 147.140 13.650 ;
        RECT 154.090 13.320 154.390 14.310 ;
        RECT 148.100 12.980 148.980 13.320 ;
        RECT 153.800 13.250 154.680 13.320 ;
        RECT 153.760 12.980 154.680 13.250 ;
        RECT 153.760 12.910 154.640 12.980 ;
        RECT 146.260 11.910 147.140 12.250 ;
        RECT 148.090 12.200 148.970 12.540 ;
        RECT 150.790 12.200 151.670 12.540 ;
        RECT 152.890 12.250 153.190 12.300 ;
        RECT 152.560 11.910 153.440 12.250 ;
        RECT 152.890 11.720 153.190 11.910 ;
        RECT 148.100 11.380 148.980 11.720 ;
        RECT 152.600 11.380 153.480 11.720 ;
        RECT 148.090 10.600 148.970 10.940 ;
        RECT 150.790 10.600 151.670 10.940 ;
        RECT 148.090 9.800 148.970 10.140 ;
        RECT 145.090 9.650 145.390 9.700 ;
        RECT 144.760 9.310 145.640 9.650 ;
        RECT 146.260 9.310 147.140 9.650 ;
        RECT 133.140 6.980 134.020 7.320 ;
        RECT 141.650 6.395 141.990 6.600 ;
        RECT 141.615 6.005 142.065 6.395 ;
        RECT 141.650 5.720 141.990 6.005 ;
        RECT 145.090 5.650 145.390 9.310 ;
        RECT 146.300 8.850 147.180 8.920 ;
        RECT 146.260 8.580 147.180 8.850 ;
        RECT 146.260 8.510 147.140 8.580 ;
        RECT 148.090 8.200 148.970 8.540 ;
        RECT 150.790 8.200 151.670 8.540 ;
        RECT 148.090 7.400 148.970 7.740 ;
        RECT 150.790 7.400 151.670 7.740 ;
        RECT 148.090 6.600 148.970 6.940 ;
        RECT 150.790 6.600 151.670 6.940 ;
        RECT 148.370 6.120 148.710 6.390 ;
        RECT 148.100 5.780 148.980 6.120 ;
        RECT 144.760 5.310 145.640 5.650 ;
        RECT 146.260 5.310 147.140 5.650 ;
        RECT 148.370 5.510 148.710 5.780 ;
        RECT 145.090 4.520 145.390 5.310 ;
        RECT 148.090 5.000 148.970 5.340 ;
        RECT 150.790 5.000 151.670 5.340 ;
        RECT 144.800 4.180 145.680 4.520 ;
        RECT 148.100 4.180 148.980 4.520 ;
        RECT 140.450 3.395 140.790 3.600 ;
        RECT 146.300 3.450 147.180 3.520 ;
        RECT 140.415 3.005 140.865 3.395 ;
        RECT 146.260 3.180 147.180 3.450 ;
        RECT 148.090 3.400 148.970 3.740 ;
        RECT 150.790 3.400 151.670 3.740 ;
        RECT 146.260 3.110 147.140 3.180 ;
        RECT 140.450 2.720 140.790 3.005 ;
        RECT 148.090 2.600 148.970 2.940 ;
        RECT 150.790 2.600 151.670 2.940 ;
        RECT 121.100 1.830 121.980 2.170 ;
        RECT 136.750 1.830 137.630 2.170 ;
        RECT 148.090 1.800 148.970 2.140 ;
        RECT 150.790 1.800 151.670 2.140 ;
        RECT 0.500 0.050 155.020 0.950 ;
      LAYER met2 ;
        RECT 0.650 108.635 1.850 109.385 ;
        RECT 142.600 109.210 143.480 109.230 ;
        RECT 142.560 108.890 143.480 109.210 ;
        RECT 142.560 108.870 143.440 108.890 ;
        RECT 150.750 108.870 151.630 109.210 ;
        RECT 36.500 107.050 37.380 107.930 ;
        RECT 44.500 107.050 45.380 107.930 ;
        RECT 52.500 107.050 53.380 107.930 ;
        RECT 139.250 107.400 139.590 107.650 ;
        RECT 119.950 107.100 139.590 107.400 ;
        RECT 119.950 106.490 120.250 107.100 ;
        RECT 139.250 106.770 139.590 107.100 ;
        RECT 112.860 105.270 113.200 106.150 ;
        RECT 119.930 105.610 120.270 106.490 ;
        RECT 115.140 100.300 116.020 100.320 ;
        RECT 133.140 100.300 134.020 100.320 ;
        RECT 101.360 99.840 102.240 100.180 ;
        RECT 115.140 100.000 134.020 100.300 ;
        RECT 115.140 99.980 116.020 100.000 ;
        RECT 133.140 99.980 134.020 100.000 ;
        RECT 112.930 98.500 113.270 98.790 ;
        RECT 115.410 98.500 115.750 98.790 ;
        RECT 112.930 98.200 115.750 98.500 ;
        RECT 116.670 98.270 117.010 99.150 ;
        RECT 112.930 97.910 113.270 98.200 ;
        RECT 115.410 97.910 115.750 98.200 ;
        RECT 75.540 96.350 76.420 96.690 ;
        RECT 115.390 91.500 115.730 91.750 ;
        RECT 127.630 91.500 127.970 91.750 ;
        RECT 115.390 91.200 127.970 91.500 ;
        RECT 115.390 90.870 115.730 91.200 ;
        RECT 127.630 91.190 127.970 91.200 ;
        RECT 116.420 90.500 117.300 90.520 ;
        RECT 125.140 90.500 126.020 90.520 ;
        RECT 20.980 90.050 21.860 90.390 ;
        RECT 116.420 90.200 126.020 90.500 ;
        RECT 127.630 90.310 127.990 91.190 ;
        RECT 127.630 90.270 127.970 90.310 ;
        RECT 116.420 90.180 117.300 90.200 ;
        RECT 125.140 90.180 126.020 90.200 ;
        RECT 80.200 88.650 80.800 89.250 ;
        RECT 97.150 89.100 97.490 89.350 ;
        RECT 111.340 89.100 111.680 89.390 ;
        RECT 97.150 88.800 111.680 89.100 ;
        RECT 97.150 88.470 97.490 88.800 ;
        RECT 111.340 88.510 111.680 88.800 ;
        RECT 127.650 86.900 127.990 87.190 ;
        RECT 129.330 86.900 129.670 87.190 ;
        RECT 127.650 86.600 129.670 86.900 ;
        RECT 115.460 86.500 116.340 86.520 ;
        RECT 125.140 86.500 126.020 86.520 ;
        RECT 115.460 86.200 126.020 86.500 ;
        RECT 127.650 86.310 127.990 86.600 ;
        RECT 129.330 86.310 129.670 86.600 ;
        RECT 115.460 86.180 116.340 86.200 ;
        RECT 125.140 86.180 126.020 86.200 ;
        RECT 80.340 84.750 80.680 85.630 ;
        RECT 75.540 84.360 76.420 84.700 ;
        RECT 60.660 82.760 61.540 83.100 ;
        RECT 68.660 82.760 69.540 83.100 ;
        RECT 116.670 82.270 117.010 83.150 ;
        RECT 116.690 78.900 117.030 79.190 ;
        RECT 119.930 78.900 120.270 79.190 ;
        RECT 115.410 78.750 115.750 78.790 ;
        RECT 115.390 77.910 115.750 78.750 ;
        RECT 116.690 78.600 120.270 78.900 ;
        RECT 116.690 78.310 117.030 78.600 ;
        RECT 119.930 78.310 120.270 78.600 ;
        RECT 124.500 78.500 125.380 78.520 ;
        RECT 133.140 78.500 134.020 78.520 ;
        RECT 124.500 78.200 134.020 78.500 ;
        RECT 124.500 78.180 125.380 78.200 ;
        RECT 133.140 78.180 134.020 78.200 ;
        RECT 115.390 77.870 115.730 77.910 ;
        RECT 108.690 74.900 109.030 75.190 ;
        RECT 116.670 74.900 117.010 75.150 ;
        RECT 108.690 74.600 117.010 74.900 ;
        RECT 108.690 74.310 109.030 74.600 ;
        RECT 116.670 74.270 117.010 74.600 ;
        RECT 107.140 73.900 108.020 73.920 ;
        RECT 133.460 73.900 134.340 73.920 ;
        RECT 107.140 73.600 134.340 73.900 ;
        RECT 107.140 73.580 108.020 73.600 ;
        RECT 133.460 73.580 134.340 73.600 ;
        RECT 62.580 73.400 63.180 73.550 ;
        RECT 80.330 73.400 81.210 73.420 ;
        RECT 62.430 73.100 81.510 73.400 ;
        RECT 62.580 73.060 63.610 73.100 ;
        RECT 70.730 73.060 71.610 73.100 ;
        RECT 78.730 73.060 79.610 73.100 ;
        RECT 80.330 73.080 81.210 73.100 ;
        RECT 62.580 72.950 63.180 73.060 ;
        RECT 101.400 72.870 102.280 72.890 ;
        RECT 102.940 72.870 103.340 72.890 ;
        RECT 60.360 72.500 84.160 72.800 ;
        RECT 101.400 72.570 107.730 72.870 ;
        RECT 101.400 72.550 102.280 72.570 ;
        RECT 102.940 72.550 103.340 72.570 ;
        RECT 60.660 72.460 61.540 72.500 ;
        RECT 68.660 72.460 69.540 72.500 ;
        RECT 82.570 72.460 83.450 72.500 ;
        RECT 60.210 72.200 61.090 72.220 ;
        RECT 59.910 71.900 81.280 72.200 ;
        RECT 60.210 71.880 61.090 71.900 ;
        RECT 80.020 71.860 80.900 71.900 ;
        RECT 70.790 71.600 72.310 71.620 ;
        RECT 76.210 71.600 77.090 71.620 ;
        RECT 79.430 71.600 80.310 71.620 ;
        RECT 81.495 71.600 82.375 71.620 ;
        RECT 86.780 71.600 87.660 71.620 ;
        RECT 70.490 71.300 72.610 71.600 ;
        RECT 75.910 71.300 87.960 71.600 ;
        RECT 70.790 71.280 72.310 71.300 ;
        RECT 76.210 71.280 77.090 71.300 ;
        RECT 79.430 71.280 80.310 71.300 ;
        RECT 81.495 71.280 82.375 71.300 ;
        RECT 86.780 71.280 87.660 71.300 ;
        RECT 59.250 71.000 60.130 71.020 ;
        RECT 67.250 71.000 68.130 71.020 ;
        RECT 78.790 71.000 79.670 71.020 ;
        RECT 58.950 70.700 79.970 71.000 ;
        RECT 107.430 70.790 107.730 72.570 ;
        RECT 108.690 70.950 109.030 71.190 ;
        RECT 108.460 70.900 109.260 70.950 ;
        RECT 109.670 70.900 110.010 71.190 ;
        RECT 134.690 70.950 135.030 71.190 ;
        RECT 59.250 70.680 60.130 70.700 ;
        RECT 67.250 70.680 68.130 70.700 ;
        RECT 78.790 70.680 79.670 70.700 ;
        RECT 107.410 69.910 107.750 70.790 ;
        RECT 108.460 70.600 110.010 70.900 ;
        RECT 108.460 70.550 109.260 70.600 ;
        RECT 108.690 70.310 109.030 70.550 ;
        RECT 109.670 70.310 110.010 70.600 ;
        RECT 134.460 70.900 135.260 70.950 ;
        RECT 136.070 70.900 136.410 71.190 ;
        RECT 134.460 70.600 136.410 70.900 ;
        RECT 134.460 70.550 135.260 70.600 ;
        RECT 134.690 70.310 135.030 70.550 ;
        RECT 136.070 70.310 136.410 70.600 ;
        RECT 69.180 69.800 70.060 69.820 ;
        RECT 68.880 69.500 76.800 69.800 ;
        RECT 69.180 69.480 70.060 69.500 ;
        RECT 72.360 69.460 73.240 69.500 ;
        RECT 75.210 69.460 76.090 69.500 ;
        RECT 62.780 69.200 64.310 69.220 ;
        RECT 62.480 68.900 64.610 69.200 ;
        RECT 62.780 68.880 64.310 68.900 ;
        RECT 77.340 68.600 78.220 68.620 ;
        RECT 82.610 68.600 83.490 68.620 ;
        RECT 77.040 68.300 84.080 68.600 ;
        RECT 77.340 68.280 78.220 68.300 ;
        RECT 82.610 68.280 83.490 68.300 ;
        RECT 4.020 62.050 4.900 62.390 ;
        RECT 12.660 62.050 13.540 62.390 ;
        RECT 11.380 61.250 12.260 61.590 ;
        RECT 4.020 58.050 4.900 58.390 ;
        RECT 12.660 58.070 13.540 58.410 ;
        RECT 11.380 57.250 12.260 57.590 ;
        RECT 105.160 54.650 106.040 55.530 ;
        RECT 4.020 54.050 4.900 54.390 ;
        RECT 12.660 54.070 13.540 54.410 ;
        RECT 11.380 53.250 12.260 53.590 ;
        RECT 98.390 53.500 129.650 53.800 ;
        RECT 4.020 50.050 4.900 50.390 ;
        RECT 12.660 50.070 13.540 50.410 ;
        RECT 11.380 49.250 12.260 49.590 ;
        RECT 79.060 47.670 79.400 48.550 ;
        RECT 4.020 46.050 4.900 46.390 ;
        RECT 12.660 46.070 13.540 46.410 ;
        RECT 11.380 45.250 12.260 45.590 ;
        RECT 63.060 43.670 63.400 44.550 ;
        RECT 71.060 43.670 71.400 44.550 ;
        RECT 82.900 43.560 83.780 43.900 ;
        RECT 4.020 42.050 4.900 42.390 ;
        RECT 11.380 41.250 12.260 41.590 ;
        RECT 36.500 37.910 37.380 38.250 ;
        RECT 44.500 37.910 45.380 38.250 ;
        RECT 52.500 37.910 53.380 38.250 ;
        RECT 6.300 34.700 7.180 34.720 ;
        RECT 36.540 34.700 37.420 34.720 ;
        RECT 44.540 34.700 45.420 34.720 ;
        RECT 6.000 34.400 97.940 34.700 ;
        RECT 6.300 34.380 7.180 34.400 ;
        RECT 36.540 34.380 37.420 34.400 ;
        RECT 44.540 34.380 45.420 34.400 ;
        RECT 93.320 34.360 94.200 34.400 ;
        RECT 14.300 34.100 15.180 34.120 ;
        RECT 52.540 34.100 53.420 34.120 ;
        RECT 81.495 34.100 82.375 34.120 ;
        RECT 14.000 33.800 82.675 34.100 ;
        RECT 14.300 33.780 15.180 33.800 ;
        RECT 52.540 33.780 53.420 33.800 ;
        RECT 81.495 33.780 82.375 33.800 ;
        RECT 21.020 33.500 21.900 33.520 ;
        RECT 64.360 33.500 65.240 33.520 ;
        RECT 98.390 33.500 98.690 53.500 ;
        RECT 129.350 52.890 129.650 53.500 ;
        RECT 105.160 51.770 106.040 52.650 ;
        RECT 129.330 52.010 129.670 52.890 ;
        RECT 107.410 36.510 107.750 37.390 ;
        RECT 111.340 37.270 111.680 37.560 ;
        RECT 137.540 37.270 137.940 37.290 ;
        RECT 138.350 37.270 138.690 37.520 ;
        RECT 108.690 36.950 109.030 36.990 ;
        RECT 108.620 36.750 109.030 36.950 ;
        RECT 108.460 36.700 109.260 36.750 ;
        RECT 109.670 36.700 110.010 36.990 ;
        RECT 102.940 34.730 103.340 34.750 ;
        RECT 107.430 34.730 107.730 36.510 ;
        RECT 108.460 36.400 110.010 36.700 ;
        RECT 111.340 36.970 138.690 37.270 ;
        RECT 111.340 36.680 111.680 36.970 ;
        RECT 134.690 36.750 135.030 36.970 ;
        RECT 134.460 36.700 135.260 36.750 ;
        RECT 136.070 36.700 136.410 36.970 ;
        RECT 137.540 36.950 137.940 36.970 ;
        RECT 108.460 36.350 109.260 36.400 ;
        RECT 108.620 36.110 109.030 36.350 ;
        RECT 109.670 36.110 110.010 36.400 ;
        RECT 134.460 36.400 136.410 36.700 ;
        RECT 138.350 36.640 138.690 36.970 ;
        RECT 134.460 36.350 135.260 36.400 ;
        RECT 134.690 36.110 135.030 36.350 ;
        RECT 136.070 36.110 136.410 36.400 ;
        RECT 108.620 36.070 108.960 36.110 ;
        RECT 98.960 34.430 107.730 34.730 ;
        RECT 98.960 34.390 99.840 34.430 ;
        RECT 102.940 34.410 103.340 34.430 ;
        RECT 9.535 33.200 98.690 33.500 ;
        RECT 107.140 33.700 108.020 33.720 ;
        RECT 133.460 33.700 134.340 33.720 ;
        RECT 107.140 33.400 134.340 33.700 ;
        RECT 107.140 33.380 108.020 33.400 ;
        RECT 133.460 33.380 134.340 33.400 ;
        RECT 9.835 33.160 10.715 33.200 ;
        RECT 21.020 33.180 21.900 33.200 ;
        RECT 64.360 33.180 65.240 33.200 ;
        RECT 12.700 32.900 13.580 32.920 ;
        RECT 30.670 32.900 31.550 32.920 ;
        RECT 72.360 32.900 73.240 32.920 ;
        RECT 12.400 32.600 73.540 32.900 ;
        RECT 108.690 32.700 109.030 32.990 ;
        RECT 116.670 32.700 117.010 33.030 ;
        RECT 12.700 32.580 13.580 32.600 ;
        RECT 30.670 32.580 31.550 32.600 ;
        RECT 36.720 32.560 37.600 32.600 ;
        RECT 72.360 32.580 73.240 32.600 ;
        RECT 108.690 32.400 117.010 32.700 ;
        RECT 20.575 32.300 21.455 32.320 ;
        RECT 28.430 32.300 29.310 32.320 ;
        RECT 34.500 32.300 35.380 32.320 ;
        RECT 20.275 32.000 35.970 32.300 ;
        RECT 108.690 32.110 109.030 32.400 ;
        RECT 116.670 32.150 117.010 32.400 ;
        RECT 20.575 31.980 21.455 32.000 ;
        RECT 28.430 31.980 29.310 32.000 ;
        RECT 34.500 31.980 35.380 32.000 ;
        RECT 159.475 29.725 160.025 30.275 ;
        RECT 115.390 29.390 115.730 29.430 ;
        RECT 115.390 28.550 115.750 29.390 ;
        RECT 124.500 29.100 125.380 29.120 ;
        RECT 133.140 29.100 134.020 29.120 ;
        RECT 115.410 28.510 115.750 28.550 ;
        RECT 116.690 28.700 117.030 28.990 ;
        RECT 119.930 28.700 120.270 28.990 ;
        RECT 124.500 28.800 134.020 29.100 ;
        RECT 124.500 28.780 125.380 28.800 ;
        RECT 133.140 28.780 134.020 28.800 ;
        RECT 116.690 28.400 120.270 28.700 ;
        RECT 36.390 28.060 37.270 28.400 ;
        RECT 116.690 28.110 117.030 28.400 ;
        RECT 119.930 28.110 120.270 28.400 ;
        RECT 116.670 24.150 117.010 25.030 ;
        RECT 148.370 21.300 148.710 21.590 ;
        RECT 149.630 21.300 149.970 21.550 ;
        RECT 115.460 21.100 116.340 21.120 ;
        RECT 125.140 21.100 126.020 21.120 ;
        RECT 115.460 20.800 126.020 21.100 ;
        RECT 148.370 21.000 150.020 21.300 ;
        RECT 115.460 20.780 116.340 20.800 ;
        RECT 125.140 20.780 126.020 20.800 ;
        RECT 127.650 20.700 127.990 20.990 ;
        RECT 129.330 20.700 129.670 20.990 ;
        RECT 148.370 20.710 148.710 21.000 ;
        RECT 127.650 20.400 129.670 20.700 ;
        RECT 149.630 20.670 149.970 21.000 ;
        RECT 127.650 20.110 127.990 20.400 ;
        RECT 129.330 20.110 129.670 20.400 ;
        RECT 148.090 20.200 148.970 20.540 ;
        RECT 150.790 20.200 151.670 20.540 ;
        RECT 146.260 19.110 147.140 19.450 ;
        RECT 153.760 19.110 154.640 19.450 ;
        RECT 148.100 18.900 148.980 18.920 ;
        RECT 152.600 18.900 153.480 18.920 ;
        RECT 148.100 18.600 153.480 18.900 ;
        RECT 148.100 18.580 148.980 18.600 ;
        RECT 152.600 18.580 153.480 18.600 ;
        RECT 148.090 17.800 148.970 18.140 ;
        RECT 150.790 17.800 151.670 18.140 ;
        RECT 146.260 17.310 147.140 17.650 ;
        RECT 116.420 17.100 117.300 17.120 ;
        RECT 125.140 17.100 126.020 17.120 ;
        RECT 116.420 16.800 126.020 17.100 ;
        RECT 116.420 16.780 117.300 16.800 ;
        RECT 125.140 16.780 126.020 16.800 ;
        RECT 127.630 16.990 127.970 17.030 ;
        RECT 115.390 16.100 115.730 16.430 ;
        RECT 127.630 16.110 127.990 16.990 ;
        RECT 146.260 16.310 147.140 16.650 ;
        RECT 148.090 16.200 148.970 16.540 ;
        RECT 152.560 16.310 153.440 16.650 ;
        RECT 127.630 16.100 127.970 16.110 ;
        RECT 115.390 15.800 127.970 16.100 ;
        RECT 115.390 15.550 115.730 15.800 ;
        RECT 127.630 15.550 127.970 15.800 ;
        RECT 144.800 15.700 145.680 15.720 ;
        RECT 148.100 15.700 148.980 15.720 ;
        RECT 144.800 15.400 148.980 15.700 ;
        RECT 144.800 15.380 145.680 15.400 ;
        RECT 148.100 15.380 148.980 15.400 ;
        RECT 10.165 13.755 10.505 14.635 ;
        RECT 146.260 14.310 147.140 14.650 ;
        RECT 148.090 14.600 148.970 14.940 ;
        RECT 150.790 14.600 151.670 14.940 ;
        RECT 153.760 14.310 154.640 14.650 ;
        RECT 148.090 13.800 148.970 14.140 ;
        RECT 144.760 13.310 145.640 13.650 ;
        RECT 146.260 13.310 147.140 13.650 ;
        RECT 148.100 13.300 148.980 13.320 ;
        RECT 153.800 13.300 154.680 13.320 ;
        RECT 148.100 13.000 154.680 13.300 ;
        RECT 148.100 12.980 148.980 13.000 ;
        RECT 153.760 12.980 154.680 13.000 ;
        RECT 153.760 12.910 154.640 12.980 ;
        RECT 146.260 11.910 147.140 12.250 ;
        RECT 148.090 12.200 148.970 12.540 ;
        RECT 150.790 12.200 151.670 12.540 ;
        RECT 152.560 11.910 153.440 12.250 ;
        RECT 148.100 11.700 148.980 11.720 ;
        RECT 152.600 11.700 153.480 11.720 ;
        RECT 148.100 11.400 153.480 11.700 ;
        RECT 148.100 11.380 148.980 11.400 ;
        RECT 152.600 11.380 153.480 11.400 ;
        RECT 148.090 10.600 148.970 10.940 ;
        RECT 150.790 10.600 151.670 10.940 ;
        RECT 148.090 9.800 148.970 10.140 ;
        RECT 112.930 9.100 113.270 9.390 ;
        RECT 115.410 9.100 115.750 9.390 ;
        RECT 144.760 9.310 145.640 9.650 ;
        RECT 146.260 9.310 147.140 9.650 ;
        RECT 112.930 8.800 115.750 9.100 ;
        RECT 112.930 8.510 113.270 8.800 ;
        RECT 115.410 8.510 115.750 8.800 ;
        RECT 116.670 8.150 117.010 9.030 ;
        RECT 146.260 8.510 147.140 8.850 ;
        RECT 148.090 8.200 148.970 8.540 ;
        RECT 150.790 8.200 151.670 8.540 ;
        RECT 115.140 7.300 116.020 7.320 ;
        RECT 133.140 7.300 134.020 7.320 ;
        RECT 115.140 7.000 134.020 7.300 ;
        RECT 115.140 6.980 116.020 7.000 ;
        RECT 133.140 6.980 134.020 7.000 ;
        RECT 138.350 7.300 138.690 7.550 ;
        RECT 148.090 7.400 148.970 7.740 ;
        RECT 150.790 7.400 151.670 7.740 ;
        RECT 145.270 7.320 146.590 7.400 ;
        RECT 144.800 7.300 146.590 7.320 ;
        RECT 138.350 7.100 146.590 7.300 ;
        RECT 138.350 7.000 145.680 7.100 ;
        RECT 138.350 6.670 138.690 7.000 ;
        RECT 144.800 6.980 145.680 7.000 ;
        RECT 141.650 5.720 141.990 6.600 ;
        RECT 146.290 6.100 146.590 7.100 ;
        RECT 148.090 6.600 148.970 6.940 ;
        RECT 150.790 6.600 151.670 6.940 ;
        RECT 148.370 6.100 148.710 6.390 ;
        RECT 146.290 5.800 148.710 6.100 ;
        RECT 144.760 5.310 145.640 5.650 ;
        RECT 146.260 5.310 147.140 5.650 ;
        RECT 148.370 5.510 148.710 5.800 ;
        RECT 148.090 5.000 148.970 5.340 ;
        RECT 150.790 5.000 151.670 5.340 ;
        RECT 144.800 4.500 145.680 4.520 ;
        RECT 148.100 4.500 148.980 4.520 ;
        RECT 144.800 4.200 148.980 4.500 ;
        RECT 144.800 4.180 145.680 4.200 ;
        RECT 148.100 4.180 148.980 4.200 ;
        RECT 140.450 2.720 140.790 3.600 ;
        RECT 146.260 3.110 147.140 3.450 ;
        RECT 148.090 3.400 148.970 3.740 ;
        RECT 150.790 3.400 151.670 3.740 ;
        RECT 148.090 2.600 148.970 2.940 ;
        RECT 150.790 2.600 151.670 2.940 ;
        RECT 112.910 1.470 113.250 2.350 ;
        RECT 119.930 1.400 120.270 2.190 ;
        RECT 136.750 2.150 137.630 2.170 ;
        RECT 136.750 1.850 143.440 2.150 ;
        RECT 136.750 1.830 137.630 1.850 ;
        RECT 142.560 1.810 143.440 1.850 ;
        RECT 148.090 1.800 148.970 2.140 ;
        RECT 150.790 1.800 151.670 2.140 ;
        RECT 155.070 1.400 155.410 1.650 ;
        RECT 119.930 1.310 155.410 1.400 ;
        RECT 119.950 1.100 155.410 1.310 ;
        RECT 2.550 0.075 4.250 0.825 ;
        RECT 155.070 0.770 155.410 1.100 ;
        RECT 148.050 0.310 148.930 0.650 ;
      LAYER met3 ;
        RECT 94.025 110.220 94.575 110.320 ;
        RECT 94.025 109.920 158.650 110.220 ;
        RECT 94.025 109.820 94.575 109.920 ;
        RECT 0.650 108.635 1.850 109.385 ;
        RECT 142.560 108.870 143.520 109.250 ;
        RECT 150.750 109.060 151.710 109.250 ;
        RECT 36.500 107.050 37.460 108.010 ;
        RECT 44.500 107.050 45.460 108.010 ;
        RECT 52.500 107.050 53.460 108.010 ;
        RECT 139.250 106.770 139.630 107.730 ;
        RECT 112.860 105.270 113.240 106.230 ;
        RECT 19.080 101.370 103.190 101.380 ;
        RECT 18.600 101.080 103.190 101.370 ;
        RECT 18.600 100.990 19.560 101.080 ;
        RECT 101.360 100.180 102.320 100.220 ;
        RECT 20.280 100.170 102.320 100.180 ;
        RECT 19.800 99.880 102.320 100.170 ;
        RECT 19.800 99.790 20.760 99.880 ;
        RECT 101.360 99.840 102.320 99.880 ;
        RECT 21.480 98.970 100.790 98.980 ;
        RECT 21.000 98.680 100.790 98.970 ;
        RECT 21.000 98.590 21.960 98.680 ;
        RECT 22.680 97.770 99.590 97.780 ;
        RECT 22.200 97.480 99.590 97.770 ;
        RECT 22.200 97.390 23.160 97.480 ;
        RECT 75.540 96.650 76.500 96.730 ;
        RECT 75.540 96.350 77.100 96.650 ;
        RECT 20.980 90.350 21.940 90.430 ;
        RECT 13.920 90.050 21.940 90.350 ;
        RECT 4.020 62.350 4.980 62.430 ;
        RECT 12.660 62.350 13.620 62.430 ;
        RECT 13.920 62.350 14.220 90.050 ;
        RECT 76.800 85.050 77.100 96.350 ;
        RECT 80.200 88.650 80.800 89.250 ;
        RECT 97.100 88.470 97.530 89.430 ;
        RECT 80.340 85.050 80.720 85.710 ;
        RECT 76.800 84.750 80.720 85.050 ;
        RECT 75.540 84.360 76.500 84.740 ;
        RECT 60.660 82.760 61.620 83.140 ;
        RECT 68.660 82.760 69.620 83.140 ;
        RECT 33.380 69.850 40.580 77.450 ;
        RECT 41.380 69.850 48.580 77.450 ;
        RECT 60.990 72.840 61.290 82.760 ;
        RECT 62.580 73.440 63.180 73.550 ;
        RECT 62.580 73.060 63.690 73.440 ;
        RECT 62.580 72.950 63.360 73.060 ;
        RECT 60.660 72.460 61.620 72.840 ;
        RECT 36.530 69.450 37.430 69.850 ;
        RECT 44.530 69.450 45.430 69.850 ;
        RECT 4.020 62.050 5.580 62.350 ;
        RECT 12.660 62.050 14.220 62.350 ;
        RECT 5.280 61.550 5.580 62.050 ;
        RECT 33.380 61.850 40.580 69.450 ;
        RECT 41.380 61.850 48.580 69.450 ;
        RECT 11.380 61.550 12.340 61.630 ;
        RECT 5.280 61.250 12.340 61.550 ;
        RECT 36.530 61.450 37.430 61.850 ;
        RECT 44.530 61.450 45.430 61.850 ;
        RECT 22.440 58.450 22.820 58.780 ;
        RECT 4.020 58.350 4.980 58.430 ;
        RECT 4.020 58.050 5.580 58.350 ;
        RECT 12.660 58.150 22.820 58.450 ;
        RECT 12.660 58.070 13.620 58.150 ;
        RECT 5.280 57.550 5.580 58.050 ;
        RECT 22.440 57.820 22.820 58.150 ;
        RECT 11.380 57.550 12.340 57.630 ;
        RECT 5.280 57.250 12.340 57.550 ;
        RECT 21.240 54.450 21.620 54.780 ;
        RECT 4.020 54.350 4.980 54.430 ;
        RECT 4.020 54.050 5.580 54.350 ;
        RECT 12.660 54.150 21.620 54.450 ;
        RECT 12.660 54.070 13.620 54.150 ;
        RECT 5.280 53.550 5.580 54.050 ;
        RECT 21.240 53.820 21.620 54.150 ;
        RECT 33.380 53.850 40.580 61.450 ;
        RECT 41.380 53.850 48.580 61.450 ;
        RECT 49.380 53.850 56.580 61.450 ;
        RECT 11.380 53.550 12.340 53.630 ;
        RECT 5.280 53.250 12.340 53.550 ;
        RECT 36.530 53.450 37.430 53.850 ;
        RECT 44.530 53.450 45.430 53.850 ;
        RECT 52.530 53.450 53.430 53.850 ;
        RECT 20.040 50.450 20.420 50.780 ;
        RECT 4.020 50.350 4.980 50.430 ;
        RECT 4.020 50.050 5.580 50.350 ;
        RECT 12.660 50.150 20.420 50.450 ;
        RECT 12.660 50.070 13.620 50.150 ;
        RECT 5.280 49.550 5.580 50.050 ;
        RECT 20.040 49.820 20.420 50.150 ;
        RECT 11.380 49.550 12.340 49.630 ;
        RECT 5.280 49.250 12.340 49.550 ;
        RECT 18.840 46.450 19.220 46.780 ;
        RECT 4.020 46.350 4.980 46.430 ;
        RECT 4.020 46.050 5.580 46.350 ;
        RECT 12.660 46.150 19.220 46.450 ;
        RECT 12.660 46.070 13.620 46.150 ;
        RECT 5.280 45.550 5.580 46.050 ;
        RECT 18.840 45.820 19.220 46.150 ;
        RECT 33.380 45.850 40.580 53.450 ;
        RECT 41.380 45.850 48.580 53.450 ;
        RECT 49.380 45.850 56.580 53.450 ;
        RECT 11.380 45.550 12.340 45.630 ;
        RECT 5.280 45.250 12.340 45.550 ;
        RECT 36.530 45.450 37.430 45.850 ;
        RECT 44.530 45.450 45.430 45.850 ;
        RECT 52.530 45.450 53.430 45.850 ;
        RECT 4.020 42.350 4.980 42.430 ;
        RECT 4.020 42.050 5.580 42.350 ;
        RECT 5.280 41.550 5.580 42.050 ;
        RECT 11.380 41.550 12.340 41.630 ;
        RECT 5.280 41.250 12.340 41.550 ;
        RECT 33.380 37.850 40.580 45.450 ;
        RECT 41.380 37.850 48.580 45.450 ;
        RECT 49.380 37.850 56.580 45.450 ;
        RECT 63.060 44.630 63.360 72.950 ;
        RECT 68.990 72.840 69.290 82.760 ;
        RECT 70.730 73.060 71.690 73.440 ;
        RECT 68.660 72.460 69.620 72.840 ;
        RECT 71.060 44.630 71.360 73.060 ;
        RECT 75.540 69.840 75.840 84.360 ;
        RECT 78.730 73.060 79.690 73.440 ;
        RECT 72.360 69.410 73.320 69.840 ;
        RECT 75.210 69.460 76.170 69.840 ;
        RECT 79.060 48.630 79.360 73.060 ;
        RECT 80.350 72.240 80.650 84.750 ;
        RECT 82.570 72.460 83.530 72.840 ;
        RECT 80.020 71.860 80.980 72.240 ;
        RECT 79.060 47.670 79.440 48.630 ;
        RECT 63.060 43.670 63.440 44.630 ;
        RECT 71.060 43.670 71.440 44.630 ;
        RECT 82.900 43.940 83.200 72.460 ;
        RECT 82.900 43.560 83.860 43.940 ;
        RECT 99.290 34.770 99.590 97.480 ;
        RECT 100.490 50.150 100.790 98.680 ;
        RECT 102.890 62.450 103.190 101.080 ;
        RECT 116.670 98.270 117.050 99.230 ;
        RECT 115.390 90.870 115.770 91.830 ;
        RECT 115.430 78.830 115.730 90.870 ;
        RECT 116.710 83.230 117.010 98.270 ;
        RECT 127.630 90.270 128.010 91.830 ;
        RECT 116.670 82.270 117.050 83.230 ;
        RECT 115.390 77.870 115.770 78.830 ;
        RECT 115.430 62.450 115.730 77.870 ;
        RECT 116.710 75.230 117.010 82.270 ;
        RECT 116.670 74.270 117.050 75.230 ;
        RECT 102.890 60.200 108.340 62.450 ;
        RECT 110.340 60.200 115.740 62.450 ;
        RECT 117.740 60.200 123.140 62.450 ;
        RECT 125.140 60.200 130.540 62.450 ;
        RECT 132.540 60.200 137.940 62.450 ;
        RECT 102.890 59.300 137.940 60.200 ;
        RECT 102.890 57.450 108.340 59.300 ;
        RECT 110.340 57.450 115.740 59.300 ;
        RECT 102.890 57.150 115.740 57.450 ;
        RECT 102.940 57.050 108.340 57.150 ;
        RECT 110.340 57.050 115.740 57.150 ;
        RECT 117.740 57.050 123.140 59.300 ;
        RECT 125.140 57.050 130.540 59.300 ;
        RECT 132.540 57.050 137.940 59.300 ;
        RECT 105.160 54.650 106.120 55.610 ;
        RECT 105.160 51.690 106.120 52.650 ;
        RECT 102.940 50.150 108.340 50.250 ;
        RECT 110.340 50.150 115.740 50.250 ;
        RECT 100.490 49.850 115.740 50.150 ;
        RECT 102.940 48.000 108.340 49.850 ;
        RECT 110.340 48.000 115.740 49.850 ;
        RECT 117.740 48.000 123.140 50.250 ;
        RECT 125.140 48.000 130.540 50.250 ;
        RECT 132.540 48.000 137.940 50.250 ;
        RECT 102.940 47.100 137.940 48.000 ;
        RECT 102.940 44.850 108.340 47.100 ;
        RECT 110.340 44.850 115.740 47.100 ;
        RECT 117.740 44.850 123.140 47.100 ;
        RECT 125.140 44.850 130.540 47.100 ;
        RECT 132.540 44.850 137.940 47.100 ;
        RECT 108.620 36.070 109.000 37.030 ;
        RECT 93.320 34.310 94.280 34.740 ;
        RECT 98.960 34.390 99.920 34.770 ;
        RECT 9.835 33.160 10.795 33.540 ;
        RECT 10.165 14.715 10.465 33.160 ;
        RECT 36.720 32.560 37.680 32.940 ;
        RECT 37.050 28.440 37.350 32.560 ;
        RECT 115.430 29.430 115.730 44.850 ;
        RECT 138.350 36.640 138.730 37.600 ;
        RECT 116.670 32.070 117.050 33.030 ;
        RECT 115.390 28.470 115.770 29.430 ;
        RECT 36.390 28.060 37.350 28.440 ;
        RECT 115.430 16.430 115.730 28.470 ;
        RECT 116.710 25.030 117.010 32.070 ;
        RECT 116.670 24.070 117.050 25.030 ;
        RECT 115.390 15.470 115.770 16.430 ;
        RECT 10.165 13.755 10.545 14.715 ;
        RECT 116.710 9.030 117.010 24.070 ;
        RECT 127.630 15.470 128.010 17.030 ;
        RECT 116.670 8.070 117.050 9.030 ;
        RECT 138.390 7.630 138.690 36.640 ;
        RECT 139.290 14.030 139.590 106.770 ;
        RECT 140.400 106.050 140.780 106.530 ;
        RECT 140.400 105.570 140.790 106.050 ;
        RECT 139.200 13.400 139.590 14.030 ;
        RECT 139.200 13.070 139.580 13.400 ;
        RECT 140.490 9.230 140.790 105.570 ;
        RECT 141.600 17.700 141.980 18.030 ;
        RECT 141.600 17.070 141.990 17.700 ;
        RECT 140.400 8.270 140.790 9.230 ;
        RECT 138.350 6.670 138.730 7.630 ;
        RECT 140.490 3.680 140.790 8.270 ;
        RECT 141.690 6.680 141.990 17.070 ;
        RECT 141.650 5.720 142.030 6.680 ;
        RECT 140.450 2.720 140.830 3.680 ;
        RECT 112.910 2.000 113.290 2.430 ;
        RECT 141.690 2.000 141.990 5.720 ;
        RECT 142.890 2.190 143.190 108.870 ;
        RECT 144.000 107.250 144.380 107.730 ;
        RECT 144.000 106.770 144.390 107.250 ;
        RECT 144.090 5.700 144.390 106.770 ;
        RECT 146.260 19.110 147.220 19.490 ;
        RECT 148.090 17.950 148.970 21.550 ;
        RECT 149.630 20.670 150.010 21.630 ;
        RECT 150.330 17.950 152.130 109.060 ;
        RECT 158.350 21.600 158.650 109.920 ;
        RECT 159.475 29.725 160.025 30.275 ;
        RECT 158.075 20.750 158.925 21.600 ;
        RECT 153.760 19.110 154.720 19.490 ;
        RECT 146.260 17.310 147.220 17.690 ;
        RECT 146.260 16.310 147.220 16.690 ;
        RECT 146.260 14.310 147.220 14.690 ;
        RECT 144.760 13.310 145.720 13.690 ;
        RECT 146.260 13.310 147.220 13.690 ;
        RECT 146.260 11.910 147.220 12.290 ;
        RECT 144.760 9.310 145.720 9.690 ;
        RECT 146.260 9.310 147.220 9.690 ;
        RECT 146.260 8.510 147.220 8.890 ;
        RECT 146.290 5.700 146.670 6.240 ;
        RECT 144.090 5.690 146.710 5.700 ;
        RECT 144.090 5.400 147.220 5.690 ;
        RECT 144.760 5.310 145.720 5.400 ;
        RECT 146.260 5.310 147.220 5.400 ;
        RECT 146.290 5.280 146.670 5.310 ;
        RECT 146.260 3.110 147.220 3.490 ;
        RECT 112.910 1.700 141.990 2.000 ;
        RECT 142.560 1.810 143.520 2.190 ;
        RECT 112.910 1.470 113.290 1.700 ;
        RECT 2.550 0.075 4.250 0.825 ;
        RECT 147.630 0.500 149.430 17.950 ;
        RECT 150.790 1.550 151.670 17.950 ;
        RECT 152.560 16.310 153.520 16.690 ;
        RECT 153.760 14.310 154.720 14.690 ;
        RECT 153.790 13.300 154.170 13.840 ;
        RECT 153.790 13.290 155.410 13.300 ;
        RECT 153.760 13.000 155.410 13.290 ;
        RECT 153.760 12.910 154.720 13.000 ;
        RECT 153.790 12.880 154.170 12.910 ;
        RECT 152.560 11.910 153.520 12.290 ;
        RECT 155.110 1.730 155.410 13.000 ;
        RECT 155.070 0.770 155.450 1.730 ;
        RECT 148.050 0.310 149.010 0.500 ;
      LAYER met4 ;
        RECT 94.150 110.295 94.450 110.520 ;
        RECT 30.670 109.920 30.970 110.220 ;
        RECT 33.430 109.920 33.730 110.220 ;
        RECT 36.190 109.920 36.490 110.220 ;
        RECT 38.950 109.920 39.250 110.220 ;
        RECT 41.710 109.920 42.010 110.220 ;
        RECT 44.470 109.920 44.770 110.220 ;
        RECT 47.230 109.920 47.530 110.220 ;
        RECT 49.990 109.920 50.290 110.220 ;
        RECT 4.400 109.620 50.290 109.920 ;
        RECT 94.025 109.845 94.575 110.295 ;
        RECT 138.310 110.220 138.610 110.520 ;
        RECT 138.310 109.920 160.150 110.220 ;
        RECT 94.150 109.820 94.450 109.845 ;
        RECT 18.930 101.470 19.230 108.010 ;
        RECT 18.600 100.990 19.560 101.470 ;
        RECT 18.930 46.780 19.230 100.990 ;
        RECT 20.130 100.270 20.430 108.010 ;
        RECT 19.800 99.790 20.760 100.270 ;
        RECT 20.130 50.780 20.430 99.790 ;
        RECT 21.330 99.070 21.630 108.010 ;
        RECT 21.000 98.590 21.960 99.070 ;
        RECT 21.330 54.780 21.630 98.590 ;
        RECT 22.530 97.870 22.830 108.010 ;
        RECT 36.500 107.950 37.460 108.010 ;
        RECT 44.500 107.950 45.460 108.010 ;
        RECT 52.500 107.950 53.460 108.010 ;
        RECT 22.200 97.390 23.160 97.870 ;
        RECT 22.530 58.780 22.830 97.390 ;
        RECT 33.380 69.850 40.580 107.950 ;
        RECT 41.380 69.850 48.580 107.950 ;
        RECT 36.530 69.450 37.430 69.850 ;
        RECT 44.530 69.450 45.430 69.850 ;
        RECT 33.380 61.850 40.580 69.450 ;
        RECT 41.380 61.850 48.580 69.450 ;
        RECT 36.530 61.450 37.430 61.850 ;
        RECT 44.530 61.450 45.430 61.850 ;
        RECT 22.440 57.820 22.920 58.780 ;
        RECT 22.530 57.520 22.830 57.820 ;
        RECT 21.240 53.820 21.720 54.780 ;
        RECT 33.380 53.850 40.580 61.450 ;
        RECT 41.380 53.850 48.580 61.450 ;
        RECT 49.380 53.850 56.580 107.950 ;
        RECT 144.000 107.400 144.480 107.730 ;
        RECT 98.690 107.100 144.480 107.400 ;
        RECT 97.100 89.250 97.580 89.430 ;
        RECT 80.200 88.650 97.940 89.250 ;
        RECT 97.100 88.470 97.580 88.650 ;
        RECT 62.580 73.400 97.940 73.550 ;
        RECT 98.690 73.400 98.990 107.100 ;
        RECT 144.000 106.770 144.480 107.100 ;
        RECT 112.860 106.200 113.340 106.230 ;
        RECT 140.400 106.200 140.880 106.530 ;
        RECT 112.860 105.900 140.880 106.200 ;
        RECT 112.860 105.270 113.340 105.900 ;
        RECT 140.400 105.570 140.880 105.900 ;
        RECT 62.580 73.100 98.990 73.400 ;
        RECT 62.580 72.950 97.940 73.100 ;
        RECT 72.360 69.800 73.320 69.890 ;
        RECT 72.360 69.500 93.950 69.800 ;
        RECT 72.360 69.410 73.320 69.500 ;
        RECT 21.330 53.520 21.630 53.820 ;
        RECT 36.530 53.450 37.430 53.850 ;
        RECT 44.530 53.450 45.430 53.850 ;
        RECT 52.530 53.450 53.430 53.850 ;
        RECT 20.040 49.820 20.520 50.780 ;
        RECT 20.130 49.520 20.430 49.820 ;
        RECT 18.840 45.820 19.320 46.780 ;
        RECT 33.380 45.850 40.580 53.450 ;
        RECT 41.380 45.850 48.580 53.450 ;
        RECT 49.380 45.850 56.580 53.450 ;
        RECT 18.930 45.520 19.230 45.820 ;
        RECT 36.530 45.450 37.430 45.850 ;
        RECT 44.530 45.450 45.430 45.850 ;
        RECT 52.530 45.450 53.430 45.850 ;
        RECT 33.380 37.850 40.580 45.450 ;
        RECT 41.380 37.850 48.580 45.450 ;
        RECT 49.380 37.850 56.580 45.450 ;
        RECT 93.650 34.790 93.950 69.500 ;
        RECT 98.690 36.700 98.990 73.100 ;
        RECT 102.940 60.200 108.340 62.450 ;
        RECT 110.340 60.200 115.740 62.450 ;
        RECT 117.740 60.200 123.140 62.450 ;
        RECT 125.140 60.200 130.540 62.450 ;
        RECT 132.540 60.200 137.940 62.450 ;
        RECT 102.940 59.300 137.940 60.200 ;
        RECT 102.940 54.650 108.340 59.300 ;
        RECT 110.340 57.050 115.740 59.300 ;
        RECT 117.740 57.050 123.140 59.300 ;
        RECT 125.140 57.050 130.540 59.300 ;
        RECT 132.540 57.050 137.940 59.300 ;
        RECT 102.940 48.000 108.340 52.650 ;
        RECT 110.340 48.000 115.740 50.250 ;
        RECT 117.740 48.000 123.140 50.250 ;
        RECT 125.140 48.000 130.540 50.250 ;
        RECT 132.540 48.000 137.940 50.250 ;
        RECT 102.940 47.100 137.940 48.000 ;
        RECT 102.940 44.850 108.340 47.100 ;
        RECT 110.340 44.850 115.740 47.100 ;
        RECT 117.740 44.850 123.140 47.100 ;
        RECT 125.140 44.850 130.540 47.100 ;
        RECT 132.540 44.850 137.940 47.100 ;
        RECT 108.620 36.700 109.100 37.030 ;
        RECT 98.690 36.400 109.100 36.700 ;
        RECT 108.620 36.070 109.100 36.400 ;
        RECT 93.320 34.310 94.280 34.790 ;
        RECT 159.850 30.275 160.150 109.920 ;
        RECT 159.475 29.725 160.150 30.275 ;
        RECT 149.630 21.320 150.110 21.630 ;
        RECT 149.250 21.250 150.130 21.320 ;
        RECT 158.075 21.250 158.925 21.600 ;
        RECT 149.250 20.980 158.925 21.250 ;
        RECT 149.350 20.950 158.925 20.980 ;
        RECT 149.630 20.670 150.110 20.950 ;
        RECT 158.075 20.750 158.925 20.950 ;
        RECT 146.260 19.500 147.220 19.590 ;
        RECT 153.760 19.500 154.720 19.590 ;
        RECT 146.260 19.200 154.720 19.500 ;
        RECT 146.260 19.110 147.220 19.200 ;
        RECT 153.760 19.110 154.720 19.200 ;
        RECT 141.600 17.700 142.080 18.030 ;
        RECT 146.260 17.720 147.220 17.790 ;
        RECT 146.120 17.700 147.220 17.720 ;
        RECT 141.600 17.400 147.220 17.700 ;
        RECT 141.600 17.070 142.080 17.400 ;
        RECT 146.120 17.380 147.220 17.400 ;
        RECT 146.260 17.310 147.220 17.380 ;
        RECT 146.260 16.700 147.220 16.790 ;
        RECT 152.560 16.700 153.520 16.790 ;
        RECT 146.260 16.400 153.520 16.700 ;
        RECT 146.260 16.310 147.220 16.400 ;
        RECT 152.560 16.310 153.520 16.400 ;
        RECT 146.260 14.700 147.220 14.790 ;
        RECT 153.760 14.700 154.720 14.790 ;
        RECT 146.260 14.400 154.720 14.700 ;
        RECT 146.260 14.310 147.220 14.400 ;
        RECT 153.760 14.310 154.720 14.400 ;
        RECT 139.200 13.700 139.680 14.030 ;
        RECT 144.760 13.700 145.720 13.790 ;
        RECT 146.260 13.720 147.220 13.790 ;
        RECT 146.120 13.700 147.220 13.720 ;
        RECT 139.200 13.400 147.220 13.700 ;
        RECT 139.200 13.070 139.680 13.400 ;
        RECT 144.760 13.310 145.720 13.400 ;
        RECT 146.120 13.380 147.220 13.400 ;
        RECT 153.790 13.390 154.270 13.840 ;
        RECT 146.260 13.310 147.220 13.380 ;
        RECT 153.760 13.320 154.720 13.390 ;
        RECT 153.620 12.980 154.720 13.320 ;
        RECT 153.760 12.910 154.720 12.980 ;
        RECT 153.790 12.880 154.270 12.910 ;
        RECT 146.260 12.300 147.220 12.390 ;
        RECT 152.560 12.300 153.520 12.390 ;
        RECT 146.260 12.000 153.520 12.300 ;
        RECT 146.260 11.910 147.220 12.000 ;
        RECT 152.560 11.910 153.520 12.000 ;
        RECT 144.760 9.700 145.720 9.790 ;
        RECT 146.260 9.700 147.220 9.790 ;
        RECT 144.760 9.400 147.220 9.700 ;
        RECT 144.760 9.310 145.720 9.400 ;
        RECT 146.260 9.310 147.220 9.400 ;
        RECT 140.400 8.900 140.880 9.230 ;
        RECT 146.260 8.920 147.220 8.990 ;
        RECT 146.120 8.900 147.220 8.920 ;
        RECT 140.400 8.600 147.220 8.900 ;
        RECT 140.400 8.270 140.880 8.600 ;
        RECT 146.120 8.580 147.220 8.600 ;
        RECT 146.260 8.510 147.220 8.580 ;
        RECT 146.290 5.790 146.770 6.240 ;
        RECT 144.760 5.700 145.720 5.790 ;
        RECT 146.260 5.720 147.220 5.790 ;
        RECT 146.120 5.700 147.220 5.720 ;
        RECT 144.760 5.400 147.220 5.700 ;
        RECT 144.760 5.310 145.720 5.400 ;
        RECT 146.120 5.380 147.220 5.400 ;
        RECT 146.260 5.310 147.220 5.380 ;
        RECT 146.290 5.280 146.770 5.310 ;
        RECT 146.260 3.520 147.220 3.590 ;
        RECT 146.120 3.180 147.220 3.520 ;
        RECT 146.260 3.110 147.220 3.180 ;
        RECT 146.420 0.850 146.720 3.110 ;
        RECT 159.850 0.850 160.150 29.725 ;
        RECT 146.420 0.550 160.150 0.850 ;
  END
END tt_um_lelo_temp_wulffern
END LIBRARY

